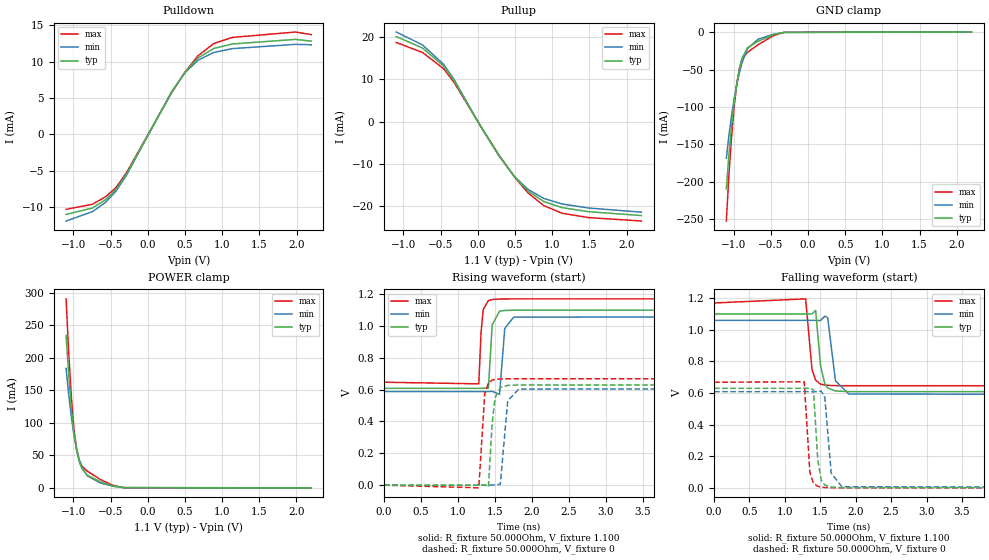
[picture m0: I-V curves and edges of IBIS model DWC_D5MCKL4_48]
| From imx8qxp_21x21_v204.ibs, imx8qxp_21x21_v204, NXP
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[Model] DWC_D5MCKL4_48
Model_type   I/O
Polarity   Non-Inverting
Enable   Active-High
C_comp   1.321pF   1.237pF   1.427pF
C_comp_pullup   305.148fF   286.138fF   319.726fF
C_comp_pulldown 1.003pF   942.855fF   1.120pF
Vinh = 396.000mV
Vinl = 216.000mV
Vmeas = 306.000mV
Vref = 306.000mV
Rref = 50Ohms
Cref = 0pF
[Model Spec]
Vinh   396.000mV   384.000mV   415.000mV
Vinl   216.000mV   204.000mV   235.000mV
Vmeas   306.000mV   294.000mV   325.000mV
Vref   306.000mV   294.000mV   325.000mV
D_overshoot_ampl_h 0.35 NA   NA
D_overshoot_ampl_l 0.35 NA   NA
D_overshoot_area_l 800.000p NA   NA
D_overshoot_area_h 800.000p NA   NA
[Receiver Thresholds]
Vcross_low = 211.000mV
Vcross_high = 401.000mV
Vdiff_ac = 140.000mV
Vdiff_dc = 140.000mV
Tdiffslew_ac = 10.000ns
[Temperature Range]   25.000   125.000   -40.000
[Voltage Range]   1.100V   1.060V   1.170V
[GND Clamp Reference]   0.00V   0.00V   0.00V
|[C Comp Corner]
| variable   typ   min   max
|C_comp 1.321pF   1.427pF   1.237pF
|C_comp_pullup 305.148fF   319.726fF   286.138fF
|C_comp_pulldown 1.003pF   1.120pF   942.855fF
[Pulldown Reference]   0.00V   0.00V   0.00V
[POWER Clamp Reference]   1.100V   1.060V   1.170V
[Pullup Reference]   1.100V   1.060V   1.170V
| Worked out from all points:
|   slope of the pulldown table from 0 to 0.165 V, typ, clamps not added: 53.8 ohm
|   slope of the pullup table from 0 to 0.165 V, typ, clamps not added: 34.5 ohm
|   GND clamp passes 1 mA (typ) near -0.36 V on its own axis
|   POWER clamp passes 1 mA (typ) near -0.39 V on its own axis
|   rising waveform, R_fixture 50.000Ohm, V_fixture 1.100: 20-80 % time 38.2ps typ, 43.8ps min, 35.6ps max; typ from 0.608 V to 1.1 V
|   rising waveform, R_fixture 50.000Ohm, V_fixture 0: 20-80 % time 54.8ps typ, 62.8ps min, 48.9ps max; typ from 0 V to 0.63 V
|   falling waveform, R_fixture 50.000Ohm, V_fixture 1.100: 20-80 % time 72.5ps typ, 82.2ps min, 66ps max; typ from 1.1 V to 0.608 V
|   falling waveform, R_fixture 50.000Ohm, V_fixture 0: 20-80 % time 54.3ps typ, 63.4ps min, 47.8ps max; typ from 0.63 V to 0 V
[GND Clamp]
-1.099V   -209.2mA   -168.4mA   -252.1mA
-1.064V   -163.4mA   -137.7mA   -190.3mA
-1.028V   -124.9mA   -111.2mA   -139.2mA
-992.7mV  -93.53mA   -88.68mA   -98.97mA
-957.3mV  -68.45mA   -69.71mA   -68.58mA
-921.8mV  -48.89mA   -53.8mA    -47.45mA
-886.4mV  -34.72mA   -40.61mA   -35.66mA
-815.5mV  -21.1mA    -22.26mA   -27.15mA
-673.6mV  -12.42mA   -9.691mA   -17.09mA
-460.9mV  -3.348mA   -2.898mA   -4.568mA
-319.1mV  -385.7uA   -561.1uA   -390.5uA
2.198V    36.46nA    642nA      5.339nA
[Power Clamp]
-1.098V   234.6mA    183.9mA    290.8mA
-1.063V   174.2mA    143.9mA    208.3mA
-1.027V   123.2mA    109.2mA    139.7mA
-991.8mV  84.12mA    80.63mA    90.23mA
-956.4mV  57.38mA    58.87mA    59.68mA
-920.9mV  40.3mA     43.02mA    42.62mA
-885.5mV  29.76mA    31.87mA    33.77mA
-814.5mV  19.66mA    18.65mA    25.86mA
-637.3mV  9.272mA    7.463mA    12.87mA
-460mV    2.471mA    2.346mA    3.441mA
-318.2mV  227.1uA    402.8uA    250.8uA
2.199V    -18.43nA   -638.2nA   -2.113nA
[Pulldown]
-1.099V   -11mA      -11.9mA    -10.3mA
-744.5mV  -10.11mA   -10.61mA   -9.6mA
-567.3mV  -8.97mA    -9.324mA   -8.566mA
-425.5mV  -7.553mA   -7.776mA   -7.28mA
-283.6mV  -5.379mA   -5.558mA   -5.21mA
319.1mV   5.761mA    5.84mA     5.69mA
496.4mV   8.469mA    8.419mA    8.5mA
673.6mV   10.48mA    10.17mA    10.77mA
886.4mV   11.79mA    11.24mA    12.47mA
1.135V    12.41mA    11.77mA    13.31mA
1.986V    13.04mA    12.36mA    14.05mA
2.198V    12.8mA     12.3mA     13.7mA
[Pullup]
-1.098V   20.2mA     21.27mA    18.8mA
-743.6mV  17.46mA    18.21mA    16.41mA
-460mV    13.2mA     13.59mA    12.56mA
-318.2mV  9.631mA    9.952mA    9.251mA
36.4mV    -1.076mA   -1.11mA    -1.046mA
284.5mV   -8.06mA    -8.175mA   -7.95mA
497.3mV   -13.2mA    -13.13mA   -13.27mA
674.5mV   -16.48mA   -16.09mA   -16.92mA
887.3mV   -18.98mA   -18.25mA   -19.96mA
1.135V    -20.43mA   -19.56mA   -21.76mA
1.49V     -21.39mA   -20.51mA   -22.79mA
2.199V    -22.3mA    -21.5mA    -23.6mA
[Ramp]
R_load=50.000Ohm
dV/dt_r   336.540mV/47.500ps  324.179mV/54.000ps  357.570mV/43.500ps
dV/dt_f   336.540mV/64.500ps  324.209mV/73.500ps  357.570mV/58.000ps
[Rising waveform]
R_fixture=50.000Ohm
V_fixture=1.100
V_fixture_min=1.060
V_fixture_max=1.170
0s        608.3mV    588.1mV    646.5mV
1.283ns   608.2mV    588.1mV    636.4mV
1.313ns   608.3mV    588.1mV    956.1mV
1.343ns   609.3mV    588.1mV    1.103V
1.413ns   609mV      588mV      1.16V
1.464ns   1.007V     589.4mV    1.166V
1.564ns   1.093V     569.7mV    1.169V
1.634ns   1.097V     983.8mV    1.169V
1.754ns   1.099V     1.055V     1.17V
10ns      1.1V       1.06V      1.17V
[Rising waveform]
R_fixture=50.000Ohm
V_fixture=0
0s        139.5nV    4.128uV    20.06nV
1.283ns   -42.78uV   4.932uV    -16.83mV
1.363ns   1.5mV      -8.145uV   573.4mV
1.413ns   -10.97mV   -119.2uV   643.5mV
1.464ns   389.1mV    983.5uV    659.8mV
1.504ns   550.2mV    1.243mV    664mV
1.574ns   614.2mV    5.149mV    666.7mV
1.674ns   626.7mV    529.7mV    667.9mV
1.824ns   629.2mV    603.1mV    668.4mV
10ns      630.1mV    608.7mV    668.4mV
[Falling waveform]
R_fixture=50.000Ohm
V_fixture=1.100
V_fixture_min=1.060
V_fixture_max=1.170
0s        1.1V       1.06V      1.17V
1.293ns   1.1V       1.06V      1.196V
1.383ns   1.101V     1.06V      748.4mV
1.434ns   1.123V     1.06V      681.2mV
1.504ns   771.7mV    1.059V     656.2mV
1.564ns   657.9mV    1.087V     650.4mV
1.604ns   632.3mV    1.077V     648.8mV
1.714ns   613.2mV    676.9mV    647mV
1.904ns   609mV      593.8mV    646.3mV
10ns      608.2mV    588mV      646.4mV
[Falling waveform]
R_fixture=50.000Ohm
V_fixture=0
0s        630mV      608.7mV    668.3mV
1.273ns   630mV      608.7mV    671.1mV
1.353ns   630.1mV    608.7mV    96.78mV
1.403ns   620.4mV    608.7mV    29.34mV
1.464ns   179mV      608.3mV    9.65mV
1.514ns   48.39mV    612.6mV    4.55mV
1.564ns   18mV       572.3mV    2.3mV
1.654ns   5.236mV    93mV       761.5uV
1.804ns   1.084mV    7.236mV    152.7uV
10ns      394.6nV    4.162uV    59.28nV
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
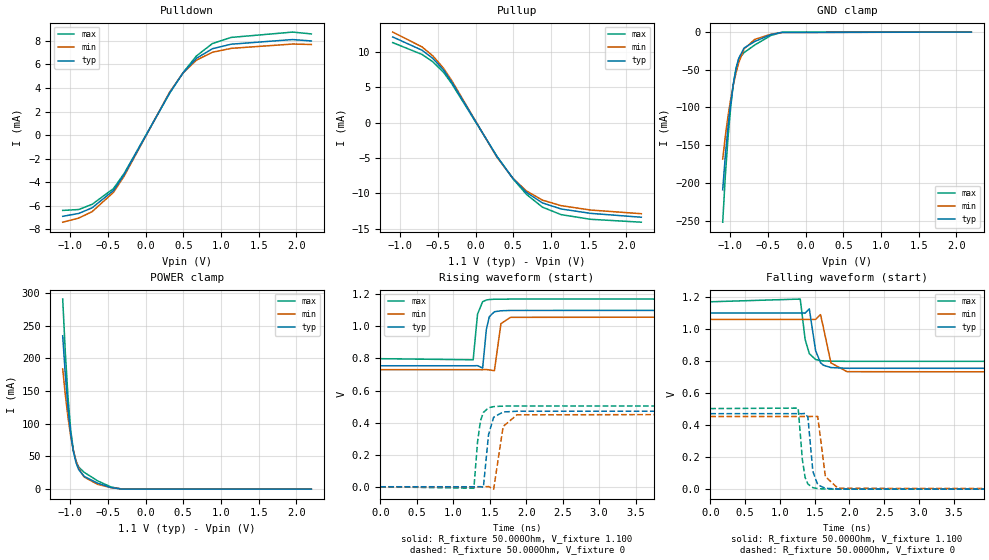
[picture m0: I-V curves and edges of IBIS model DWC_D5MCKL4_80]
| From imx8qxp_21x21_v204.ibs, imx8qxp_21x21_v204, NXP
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[Model] DWC_D5MCKL4_80
Model_type   I/O
Polarity   Non-Inverting
Enable   Active-High
C_comp   1.321pF   1.237pF   1.427pF
C_comp_pullup   304.579fF   285.377fF   319.196fF
C_comp_pulldown 1.005pF   946.034fF   1.122pF
Vinh = 390.000mV
Vinl = 210.000mV
Vmeas = 300.000mV
Vref = 300.000mV
Rref = 50Ohms
Cref = 0pF
[Model Spec]
Vinh   390.000mV   379.000mV   409.000mV
Vinl   210.000mV   199.000mV   229.000mV
Vmeas   300.000mV   289.000mV   319.000mV
Vref   300.000mV   289.000mV   319.000mV
D_overshoot_ampl_h 0.35 NA   NA
D_overshoot_ampl_l 0.35 NA   NA
D_overshoot_area_l 800.000p NA   NA
D_overshoot_area_h 800.000p NA   NA
[Receiver Thresholds]
Vcross_low = 205.000mV
Vcross_high = 395.000mV
Vdiff_ac = 140.000mV
Vdiff_dc = 140.000mV
Tdiffslew_ac = 10.000ns
[Temperature Range]   25.000   125.000   -40.000
[Voltage Range]   1.100V   1.060V   1.170V
[GND Clamp Reference]   0.00V   0.00V   0.00V
|[C Comp Corner]
| variable   typ   min   max
|C_comp 1.321pF   1.427pF   1.237pF
|C_comp_pullup 304.579fF   319.196fF   285.377fF
|C_comp_pulldown 1.005pF   1.122pF   946.034fF
[Pulldown Reference]   0.00V   0.00V   0.00V
[POWER Clamp Reference]   1.100V   1.060V   1.170V
[Pullup Reference]   1.100V   1.060V   1.170V
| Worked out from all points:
|   slope of the pulldown table from 0 to 0.165 V, typ, clamps not added: 86.4 ohm
|   slope of the pullup table from 0 to 0.165 V, typ, clamps not added: 57.5 ohm
|   GND clamp passes 1 mA (typ) near -0.36 V on its own axis
|   POWER clamp passes 1 mA (typ) near -0.39 V on its own axis
|   rising waveform, R_fixture 50.000Ohm, V_fixture 1.100: 20-80 % time 48.7ps typ, 54.4ps min, 45.9ps max; typ from 0.754 V to 1.1 V
|   rising waveform, R_fixture 50.000Ohm, V_fixture 0: 20-80 % time 71.6ps typ, 80.5ps min, 65ps max; typ from 0 V to 0.471 V
|   falling waveform, R_fixture 50.000Ohm, V_fixture 1.100: 20-80 % time 85.2ps typ, 95.9ps min, 79.5ps max; typ from 1.1 V to 0.754 V
|   falling waveform, R_fixture 50.000Ohm, V_fixture 0: 20-80 % time 64ps typ, 73.8ps min, 57.6ps max; typ from 0.471 V to 0 V
[GND Clamp]
-1.099V   -209.2mA   -168.4mA   -252.1mA
-1.064V   -163.4mA   -137.7mA   -190.3mA
-1.028V   -124.9mA   -111.2mA   -139.2mA
-992.7mV  -93.53mA   -88.68mA   -98.97mA
-957.3mV  -68.45mA   -69.71mA   -68.58mA
-921.8mV  -48.89mA   -53.8mA    -47.45mA
-886.4mV  -34.72mA   -40.61mA   -35.66mA
-815.5mV  -21.1mA    -22.26mA   -27.15mA
-673.6mV  -12.42mA   -9.691mA   -17.09mA
-460.9mV  -3.348mA   -2.898mA   -4.568mA
-319.1mV  -385.7uA   -561.1uA   -390.5uA
2.198V    36.46nA    642nA      5.339nA
[Power Clamp]
-1.098V   234.6mA    183.9mA    290.8mA
-1.063V   174.2mA    143.9mA    208.3mA
-1.027V   123.2mA    109.2mA    139.7mA
-991.8mV  84.12mA    80.63mA    90.23mA
-956.4mV  57.38mA    58.87mA    59.68mA
-920.9mV  40.3mA     43.02mA    42.62mA
-885.5mV  29.76mA    31.87mA    33.77mA
-814.5mV  19.66mA    18.65mA    25.86mA
-637.3mV  9.272mA    7.463mA    12.87mA
-460mV    2.471mA    2.346mA    3.441mA
-318.2mV  227.1uA    402.8uA    250.8uA
2.199V    -18.43nA   -638.2nA   -2.113nA
[Pulldown]
-1.099V   -6.9mA     -7.4mA     -6.4mA
-886.4mV  -6.658mA   -7.05mA    -6.323mA
-709.1mV  -6.179mA   -6.505mA   -5.883mA
-425.5mV  -4.706mA   -4.866mA   -4.544mA
-283.6mV  -3.353mA   -3.477mA   -3.253mA
319.1mV   3.591mA    3.654mA    3.552mA
496.4mV   5.277mA    5.269mA    5.306mA
673.6mV   6.526mA    6.368mA    6.724mA
886.4mV   7.34mA     7.038mA    7.781mA
1.135V    7.725mA    7.372mA    8.301mA
1.95V     8.12mA     7.738mA    8.754mA
2.198V    8mA        7.7mA      8.6mA
[Pullup]
-1.098V   12.1mA     12.79mA    11.3mA
-708.2mV  10.22mA    10.69mA    9.626mA
-566.4mV  9.072mA    9.431mA    8.592mA
-424.5mV  7.435mA    7.687mA    7.106mA
-318.2mV  5.772mA    5.99mA     5.553mA
284.5mV   -4.83mA    -4.92mA    -4.772mA
497.3mV   -7.909mA   -7.898mA   -7.961mA
674.5mV   -9.874mA   -9.678mA   -10.15mA
887.3mV   -11.37mA   -10.98mA   -11.97mA
1.135V    -12.23mA   -11.76mA   -13.03mA
1.526V    -12.85mA   -12.38mA   -13.69mA
2.199V    -13.4mA    -12.9mA    -14.1mA
[Ramp]
R_load=50.000Ohm
dV/dt_r   245.130mV/60.500ps  235.168mV/68.500ps  262.470mV/56.000ps
dV/dt_f   245.100mV/75.500ps  235.168mV/86.000ps  262.470mV/69.500ps
[Rising waveform]
R_fixture=50.000Ohm
V_fixture=1.100
V_fixture_min=1.060
V_fixture_max=1.170
0s        754.3mV    729.9mV    798.4mV
1.273ns   754.3mV    729.9mV    791.5mV
1.333ns   754.8mV    729.9mV    1.076V
1.403ns   740mV      729.8mV    1.154V
1.454ns   981.2mV    730.7mV    1.164V
1.494ns   1.06V      728.4mV    1.167V
1.564ns   1.091V     723.6mV    1.169V
1.654ns   1.097V     1.017V     1.169V
1.784ns   1.099V     1.056V     1.17V
10ns      1.1V       1.06V      1.17V
[Rising waveform]
R_fixture=50.000Ohm
V_fixture=0
0s        170.7nV    5.063uV    24.44nV
1.283ns   -33.32uV   5.741uV    -9.412mV
1.333ns   263.4uV    21.19uV    279.3mV
1.373ns   429uV      -23.08uV   410.8mV
1.413ns   -3.922mV   -91.12uV   463.2mV
1.484ns   325.6mV    1.08mV     492.4mV
1.554ns   433.7mV    -15.02mV   499.7mV
1.684ns   466.1mV    376.2mV    502.8mV
1.874ns   470.7mV    448.4mV    503.5mV
10ns      471.4mV    453.8mV    503.3mV
[Falling waveform]
R_fixture=50.000Ohm
V_fixture=1.100
V_fixture_min=1.060
V_fixture_max=1.170
0s        1.1V       1.06V      1.17V
1.293ns   1.1V       1.06V      1.187V
1.363ns   1.099V     1.06V      935.2mV
1.423ns   1.126V     1.06V      846mV
1.514ns   864.3mV    1.06V      809.7mV
1.584ns   790mV      1.09V      802.6mV
1.624ns   774.2mV    1.012V     800.9mV
1.734ns   759.2mV    788.1mV    799mV
1.965ns   754.8mV    733.7mV    798.2mV
10ns      754.3mV    729.8mV    798.3mV
[Falling waveform]
R_fixture=50.000Ohm
V_fixture=0
0s        471.3mV    453.7mV    503.2mV
1.263ns   471.3mV    453.7mV    506.2mV
1.323ns   471.2mV    453.7mV    186.6mV
1.363ns   472.8mV    453.7mV    72.43mV
1.403ns   449.3mV    453.7mV    31.85mV
1.474ns   111.8mV    453.9mV    9.481mV
1.544ns   27.15mV    453.7mV    3.436mV
1.654ns   5.633mV    78.82mV    846uV
1.834ns   837.6uV    5.569mV    118.7uV
10ns      308.7nV    5.349uV    127.6nV
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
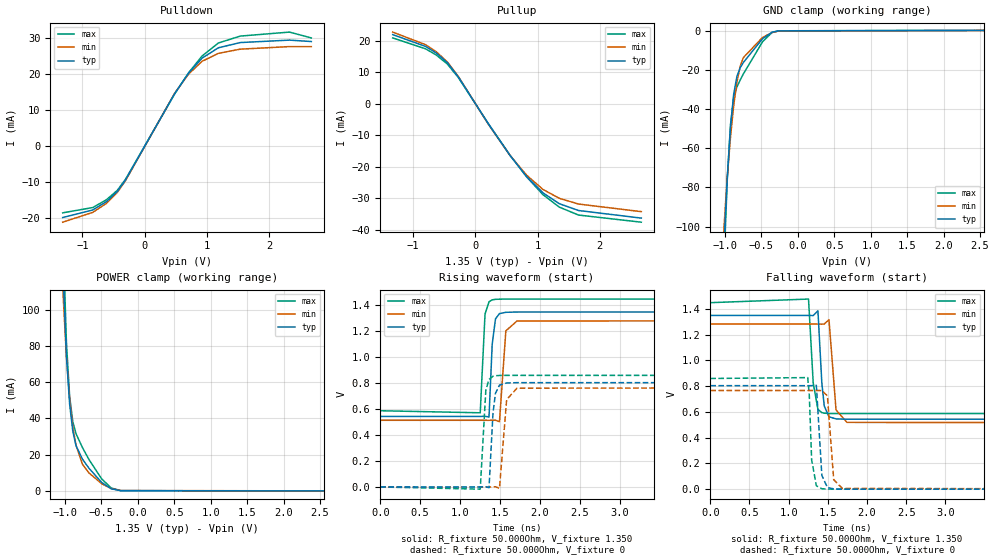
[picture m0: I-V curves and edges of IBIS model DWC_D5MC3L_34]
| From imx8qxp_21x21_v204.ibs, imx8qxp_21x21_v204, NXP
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[Model] DWC_D5MC3L_34
Model_type   I/O
Polarity   Non-Inverting
Enable   Active-High
C_comp   1.262pF   1.180pF   1.365pF
C_comp_pullup   279.441fF   258.852fF   306.885fF
C_comp_pulldown 973.651fF   908.565fF   1.053pF
Vinh = 800.000mV
Vinl = 550.000mV
Vmeas = 675.000mV
Vref = 675.000mV
Rref = 50Ohms
Cref = 0pF
[Model Spec]
Vinh   800.000mV   766.500mV   850.000mV
Vinl   550.000mV   516.500mV   600.000mV
Vmeas   675.000mV   641.500mV   725.000mV
Vref   675.000mV   641.500mV   725.000mV
D_overshoot_ampl_h 0.4 NA   NA
D_overshoot_ampl_l 0.4 NA   NA
D_overshoot_area_l 100.000p NA   NA
D_overshoot_area_h 100.000p NA   NA
[Receiver Thresholds]
Vth = 675.000mV
Vth_min = 661.500mV
Vth_max = 688.500mV
Vinh_ac = 125.000mV
Vinh_dc = 90.000mV
Vinl_ac = -125.000mV
Vinl_dc = -90.000mV
Tslew_ac = 5.000ns
Threshold_sensitivity = 0.5
Reference_supply Pullup_ref
[Temperature Range]   25.000   125.000   -40.000
[Voltage Range]   1.350V   1.283V   1.450V
[GND Clamp Reference]   0.00V   0.00V   0.00V
|[C Comp Corner]
| variable   typ   min   max
|C_comp 1.262pF   1.365pF   1.180pF
|C_comp_pullup 279.441fF   306.885fF   258.852fF
|C_comp_pulldown 973.651fF   1.053pF   908.565fF
[Pulldown Reference]   0.00V   0.00V   0.00V
[POWER Clamp Reference]   1.350V   1.283V   1.450V
[Pullup Reference]   1.350V   1.283V   1.450V
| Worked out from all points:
|   slope of the pulldown table from 0 to 0.203 V, typ, clamps not added: 32.3 ohm
|   slope of the pullup table from 0 to 0.203 V, typ, clamps not added: 32.7 ohm
|   GND clamp passes 1 mA (typ) near -0.36 V on its own axis
|   POWER clamp passes 1 mA (typ) near -0.36 V on its own axis
|   rising waveform, R_fixture 50.000Ohm, V_fixture 1.350: 20-80 % time 37ps typ, 42.6ps min, 34.5ps max; typ from 0.544 V to 1.35 V
|   rising waveform, R_fixture 50.000Ohm, V_fixture 0: 20-80 % time 44.6ps typ, 52.6ps min, 41ps max; typ from 0 V to 0.804 V
|   falling waveform, R_fixture 50.000Ohm, V_fixture 1.350: 20-80 % time 47.4ps typ, 53.9ps min, 44.2ps max; typ from 1.35 V to 0.544 V
|   falling waveform, R_fixture 50.000Ohm, V_fixture 0: 20-80 % time 38.8ps typ, 45.4ps min, 35.4ps max; typ from 0.804 V to 0 V
[GND Clamp]
-1.318V   -593.4mA   -427mA     -758.7mA
-1.011V   -108.7mA   -99.8mA    -118.2mA
-966.7mV  -74.7mA    -74.6mA    -75.87mA
-922.7mV  -49.41mA   -54.3mA    -47.9mA
-878.8mV  -32.42mA   -38.21mA   -34.12mA
-834.8mV  -23.33mA   -26.23mA   -28.72mA
-790.9mV  -19.01mA   -18.35mA   -25.26mA
-747mV    -16.25mA   -13.76mA   -22.11mA
-483.3mV  -4.093mA   -3.434mA   -5.633mA
-351.5mV  -766.8uA   -911.3uA   -894.7uA
-263.6mV  -79.41uA   -192.1uA   -51.43uA
2.68V     154.9uA    127.3uA    193.1uA
[Power Clamp]
-1.33V    727.8mA    510.6mA    954.1mA
-1.023V   119.4mA    107.4mA    137.5mA
-978.8mV  74.87mA    74.2mA     82.23mA
-934.8mV  47.95mA    50.66mA    52.21mA
-890.9mV  32.9mA     35.12mA    38.1mA
-847mV    24.9mA     25.11mA    31.53mA
-759.1mV  17.5mA     14.71mA    23.9mA
-671.2mV  12.54mA    9.915mA    17.38mA
-495.5mV  4.603mA    3.922mA    6.563mA
-363.6mV  1.088mA    1.21mA     1.541mA
-231.8mV  46.56uA    141.4uA    53.69uA
2.668V    -76.24uA   -66.58uA   -87.76uA
[Pulldown]
-1.318V   -20mA      -21.3mA    -18.7mA
-834.8mV  -17.9mA    -18.57mA   -17.23mA
-615.2mV  -15.6mA    -16.07mA   -15.07mA
-439.4mV  -12.76mA   -13.01mA   -12.44mA
-307.6mV  -9.544mA   -9.743mA   -9.357mA
483.3mV   14.46mA    14.56mA    14.37mA
703mV     20.04mA    19.79mA    20.15mA
922.7mV   24.29mA    23.41mA    24.89mA
1.186V    27.17mA    25.62mA    28.5mA
1.538V    28.62mA    26.79mA    30.42mA
2.329V    29.3mA     27.5mA     31.53mA
2.68V     28.9mA     27.5mA     29.9mA
[Pullup]
-1.33V    22mA       22.8mA     20.95mA
-803mV    18.26mA    18.81mA    17.5mA
-627.3mV  16.13mA    16.52mA    15.49mA
-451.5mV  13.09mA    13.31mA    12.65mA
-275.8mV  8.586mA    8.754mA    8.383mA
207.6mV   -6.353mA   -6.458mA   -6.264mA
559.1mV   -16.46mA   -16.46mA   -16.39mA
822.7mV   -23.06mA   -22.65mA   -23.2mA
1.086V    -28.28mA   -27.19mA   -28.85mA
1.35V     -31.73mA   -30.02mA   -32.82mA
1.658V    -33.89mA   -31.83mA   -35.33mA
2.668V    -36.3mA    -34.25mA   -37.6mA
[Ramp]
R_load=50.000Ohm
dV/dt_r   482.550mV/41.000ps  460.168mV/48.000ps  515.970mV/38.000ps
dV/dt_f   482.550mV/43.500ps  460.198mV/49.500ps  515.970mV/40.000ps
[Rising waveform]
R_fixture=50.000Ohm
V_fixture=1.350
V_fixture_min=1.283
V_fixture_max=1.450
0s        543.7mV    513.9mV    587.5mV
1.253ns   543.7mV    513.9mV    571.7mV
1.313ns   544.8mV    513.9mV    1.332V
1.363ns   539.3mV    513.8mV    1.427V
1.403ns   1.099V     514.3mV    1.442V
1.444ns   1.295V     514.3mV    1.446V
1.494ns   1.336V     503.5mV    1.447V
1.574ns   1.346V     1.203V     1.448V
1.714ns   1.348V     1.279V     1.448V
10ns      1.349V     1.282V     1.448V
[Rising waveform]
R_fixture=50.000Ohm
V_fixture=0
0s        353.8nV    7.444uV    47.1nV
1.253ns   5.716uV    6.285uV    -16.79mV
1.323ns   1.561mV    21.94uV    744.3mV
1.363ns   -5.911mV   -83.11uV   829.4mV
1.413ns   569.6mV    673.4uV    853.1mV
1.444ns   722.2mV    1.526mV    857.1mV
1.494ns   784.8mV    -10.79mV   859.4mV
1.584ns   801.6mV    672.9mV    860.1mV
1.714ns   803.9mV    761.3mV    860.1mV
10ns      803.7mV    766mV      859.5mV
[Falling waveform]
R_fixture=50.000Ohm
V_fixture=1.350
V_fixture_min=1.283
V_fixture_max=1.450
0s        1.349V     1.282V     1.448V
1.253ns   1.349V     1.282V     1.476V
1.313ns   1.348V     1.282V     823.8mV
1.373ns   1.385V     1.282V     619.3mV
1.423ns   822.6mV    1.281V     594.4mV
1.454ns   645.3mV    1.282V     590mV
1.514ns   561.8mV    1.316V     587.4mV
1.604ns   545.6mV    615.1mV    586.8mV
1.744ns   543.3mV    518.2mV    586.7mV
10ns      543.6mV    513.8mV    587.4mV
[Falling waveform]
R_fixture=50.000Ohm
V_fixture=0
0s        803.6mV    766mV      859.4mV
1.243ns   803.5mV    766mV      866.2mV
1.263ns   803.6mV    766mV      728.8mV
1.293ns   803.5mV    766mV      227.1mV
1.353ns   805.8mV    766mV      26.75mV
1.423ns   106.7mV    765.5mV    3.619mV
1.494ns   12.92mV    724.6mV    554.2uV
1.574ns   2.201mV    74.43mV    70.96uV
1.684ns   233.3uV    5.586mV    9.729uV
10ns      679.5nV    7.715uV    283.7nV
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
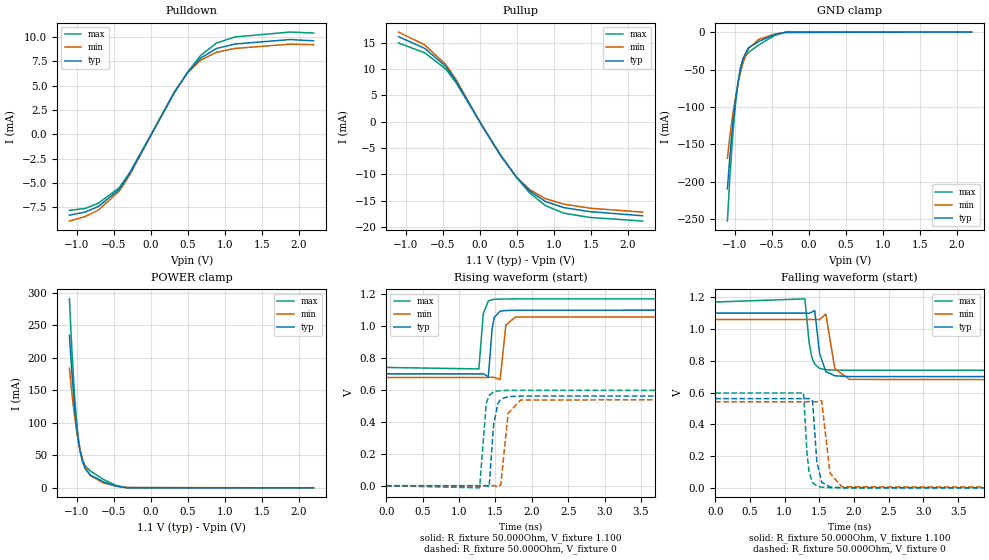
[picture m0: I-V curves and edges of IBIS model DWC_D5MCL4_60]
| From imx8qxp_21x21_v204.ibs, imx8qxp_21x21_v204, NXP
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[Model] DWC_D5MCL4_60
Model_type   I/O
Polarity   Non-Inverting
Enable   Active-High
C_comp   1.321pF   1.237pF   1.427pF
C_comp_pullup   306.026fF   287.268fF   320.532fF
C_comp_pulldown 1.001pF   938.298fF   1.118pF
Vinh = 404.000mV
Vinl = 224.000mV
Vmeas = 314.000mV
Vref = 314.000mV
Rref = 50Ohms
Cref = 0pF
[Model Spec]
Vinh   404.000mV   393.000mV   424.000mV
Vinl   224.000mV   213.000mV   244.000mV
Vmeas   314.000mV   303.000mV   334.000mV
Vref   314.000mV   303.000mV   334.000mV
[Receiver Thresholds]
Vth = 314.000mV
Vth_min = 303.000mV
Vth_max = 325.000mV
Vinh_ac = 70.000mV
Vinh_dc = 70.000mV
Vinl_ac = -70.000mV
Vinl_dc = -70.000mV
Tslew_ac = 5.000ns
Reference_supply Pullup_ref
[Temperature Range]   25.000   125.000   -40.000
[Voltage Range]   1.100V   1.060V   1.170V
[GND Clamp Reference]   0.00V   0.00V   0.00V
[Pulldown Reference]   0.00V   0.00V   0.00V
[POWER Clamp Reference]   1.100V   1.060V   1.170V
[Pullup Reference]   1.100V   1.060V   1.170V
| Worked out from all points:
|   slope of the pulldown table from 0 to 0.165 V, typ, clamps not added: 72 ohm
|   slope of the pullup table from 0 to 0.165 V, typ, clamps not added: 43.1 ohm
|   GND clamp passes 1 mA (typ) near -0.36 V on its own axis
|   POWER clamp passes 1 mA (typ) near -0.39 V on its own axis
|   rising waveform, R_fixture 50.000Ohm, V_fixture 1.100: 20-80 % time 42.7ps typ, 48.1ps min, 40ps max; typ from 0.7 V to 1.1 V
|   rising waveform, R_fixture 50.000Ohm, V_fixture 0: 20-80 % time 61.6ps typ, 70.6ps min, 55.8ps max; typ from 0 V to 0.562 V
|   falling waveform, R_fixture 50.000Ohm, V_fixture 1.100: 20-80 % time 81.5ps typ, 90.8ps min, 74.3ps max; typ from 1.1 V to 0.7 V
|   falling waveform, R_fixture 50.000Ohm, V_fixture 0: 20-80 % time 60.2ps typ, 69.6ps min, 53.5ps max; typ from 0.562 V to 0 V
[GND Clamp]
-1.099V   -209.2mA   -168.4mA   -252.1mA
-1.064V   -163.4mA   -137.7mA   -190.3mA
-1.028V   -124.9mA   -111.2mA   -139.2mA
-992.7mV  -93.53mA   -88.68mA   -98.97mA
-957.3mV  -68.45mA   -69.71mA   -68.58mA
-921.8mV  -48.89mA   -53.8mA    -47.45mA
-886.4mV  -34.72mA   -40.61mA   -35.66mA
-815.5mV  -21.1mA    -22.26mA   -27.15mA
-673.6mV  -12.42mA   -9.691mA   -17.09mA
-460.9mV  -3.348mA   -2.898mA   -4.568mA
-319.1mV  -385.7uA   -561.1uA   -390.5uA
2.198V    36.46nA    642nA      5.34nA
[Power Clamp]
-1.098V   234.6mA    183.9mA    290.8mA
-1.063V   174.2mA    143.9mA    208.3mA
-1.027V   123.2mA    109.2mA    139.7mA
-991.8mV  84.12mA    80.63mA    90.23mA
-956.4mV  57.38mA    58.87mA    59.68mA
-920.9mV  40.3mA     43.02mA    42.62mA
-885.5mV  29.76mA    31.87mA    33.77mA
-814.5mV  19.66mA    18.65mA    25.86mA
-637.3mV  9.272mA    7.463mA    12.87mA
-460mV    2.471mA    2.346mA    3.441mA
-318.2mV  227.1uA    402.8uA    250.8uA
2.199V    -18.43nA   -638.2nA   -2.114nA
[Pulldown]
-1.099V   -8.3mA     -8.9mA     -7.8mA
-886.4mV  -7.98mA    -8.444mA   -7.613mA
-709.1mV  -7.415mA   -7.784mA   -7.08mA
-425.5mV  -5.647mA   -5.823mA   -5.47mA
-283.6mV  -4.023mA   -4.162mA   -3.916mA
319.1mV   4.308mA    4.374mA    4.276mA
496.4mV   6.332mA    6.305mA    6.387mA
673.6mV   7.83mA     7.618mA    8.094mA
886.4mV   8.808mA    8.418mA    9.366mA
1.135V    9.27mA     8.817mA    9.991mA
1.879V    9.729mA    9.256mA    10.5mA
2.198V    9.6mA      9.2mA      10.4mA
[Pullup]
-1.098V   16.2mA     17.07mA    15mA
-743.6mV  13.97mA    14.62mA    13.12mA
-460mV    10.56mA    10.91mA    10.05mA
-318.2mV  7.71mA     7.989mA    7.404mA
36.4mV    -861.2uA   -890.7uA   -837.3uA
284.5mV   -6.452mA   -6.562mA   -6.362mA
497.3mV   -10.57mA   -10.53mA   -10.62mA
674.5mV   -13.2mA    -12.91mA   -13.54mA
887.3mV   -15.19mA   -14.65mA   -15.97mA
1.135V    -16.35mA   -15.69mA   -17.4mA
1.49V     -17.12mA   -16.46mA   -18.22mA
2.199V    -17.9mA    -17.21mA   -18.9mA
[Ramp]
R_load=50.000Ohm
dV/dt_r   288.630mV/53.000ps  277.409mV/60.500ps  308.010mV/49.000ps
dV/dt_f   288.600mV/71.500ps  277.378mV/80.500ps  308.010mV/64.500ps
[Rising waveform]
R_fixture=50.000Ohm
V_fixture=1.100
V_fixture_min=1.060
V_fixture_max=1.170
0s        700.1mV    677.9mV    740.6mV
1.273ns   700.1mV    677.9mV    731.4mV
1.333ns   700.7mV    677.9mV    1.078V
1.403ns   682.6mV    677.9mV    1.157V
1.454ns   980.6mV    678.9mV    1.165V
1.484ns   1.054V     678mV      1.167V
1.564ns   1.093V     664.1mV    1.169V
1.644ns   1.097V     1.007V     1.169V
1.774ns   1.099V     1.056V     1.17V
10ns      1.1V       1.06V      1.17V
[Rising waveform]
R_fixture=50.000Ohm
V_fixture=0
0s        159nV      4.711uV    22.78nV
1.283ns   -38.75uV   5.44uV     -13.34mV
1.373ns   625.5uV    -28.1uV    513.6mV
1.413ns   -8.049mV   -107.3uV   565.1mV
1.474ns   376.1mV    1.143mV    587.8mV
1.534ns   516mV      -6.508mV   593.7mV
1.574ns   541.4mV    4.836mV    595.2mV
1.674ns   557.7mV    452.9mV    596.8mV
1.844ns   561.4mV    536.8mV    597.4mV
10ns      562.2mV    542.6mV    597.3mV
[Falling waveform]
R_fixture=50.000Ohm
V_fixture=1.100
V_fixture_min=1.060
V_fixture_max=1.170
0s        1.1V       1.06V      1.17V
1.293ns   1.1V       1.06V      1.19V
1.353ns   1.099V     1.06V      916.2mV
1.393ns   1.107V     1.06V      822.1mV
1.434ns   1.117V     1.06V      778.9mV
1.504ns   847mV      1.059V     752.5mV
1.594ns   732.1mV    1.094V     743.8mV
1.724ns   705.5mV    750.7mV    741.1mV
1.935ns   700.8mV    682.9mV    740.3mV
10ns      700.1mV    677.9mV    740.5mV
[Falling waveform]
R_fixture=50.000Ohm
V_fixture=0
0s        562.1mV    542.5mV    597.2mV
1.273ns   562.1mV    542.5mV    597.5mV
1.323ns   561.9mV    542.5mV    216.4mV
1.353ns   562.3mV    542.5mV    99.98mV
1.403ns   546.3mV    542.5mV    33.31mV
1.464ns   167.8mV    542.2mV    11.31mV
1.534ns   35.1mV     549.7mV    4.017mV
1.654ns   5.95mV     92.55mV    871.9uV
1.824ns   989.9uV    6.625mV    138.5uV
10ns      592nV      5.198uV    167.7nV
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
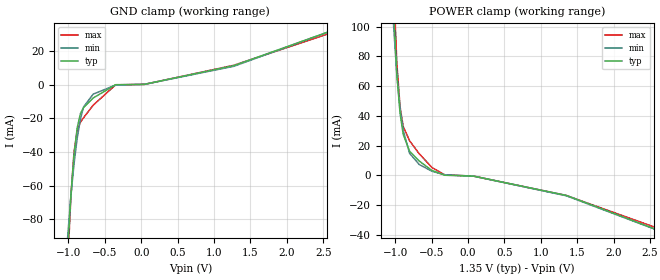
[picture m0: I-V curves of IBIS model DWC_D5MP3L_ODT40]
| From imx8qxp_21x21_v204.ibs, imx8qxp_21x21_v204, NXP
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[Model] DWC_D5MP3L_ODT40
Model_type   Input
Polarity   Non-Inverting
Enable   Active-High
C_comp   1.357pF   1.333pF   1.413pF
C_comp_power_clamp   387.694fF   369.914fF   419.877fF
C_comp_gnd_clamp 960.640fF   900.161fF   1.038pF
Vinh = 800.000mV
Vinl = 550.000mV
[Model Spec]
D_overshoot_ampl_h 0.4 NA   NA
D_overshoot_ampl_l 0.4 NA   NA
D_overshoot_area_l 100.000p NA   NA
D_overshoot_area_h 100.000p NA   NA
[Receiver Thresholds]
Vth = 675.000mV
Vth_min = 661.500mV
Vth_max = 688.500mV
Vinh_ac = 125.000mV
Vinh_dc = 90.000mV
Vinl_ac = -125.000mV
Vinl_dc = -90.000mV
Tslew_ac = 5.000ns
Threshold_sensitivity = 0.5
Reference_supply Power_clamp_ref
[Temperature Range]   25.000   125.000   -40.000
[Voltage Range]   1.350V   1.283V   1.450V
[GND Clamp Reference]   0.00V   0.00V   0.00V
[POWER Clamp Reference]   1.350V   1.283V   1.450V
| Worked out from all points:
|   GND clamp passes 1 mA (typ) near -0.43 V on its own axis
|   POWER clamp passes 1 mA (typ) near -0.40 V on its own axis
[GND Clamp]
-1.318V   -579.5mA   -413.7mA   -744.6mA
-1.011V   -99.9mA    -91.36mA   -109.1mA
-966.7mV  -66.5mA    -66.83mA   -67.5mA
-922.7mV  -41.88mA   -47.17mA   -40.22mA
-878.8mV  -25.54mA   -31.72mA   -27.11mA
-834.8mV  -17.09mA   -20.36mA   -22.34mA
-790.9mV  -13.39mA   -13.07mA   -19.5mA
-659.1mV  -7.784mA   -5.455mA   -12.06mA
-351.5mV  156.3uA    -72.56uA   68.25uA
43.94mV   369.5uA    370.1uA    360uA
1.274V    11.56mA    11.16mA    11.77mA
2.68V     33.33mA    33.38mA    32.14mA
[Power Clamp]
-1.33V    716.6mA    499.8mA    942.7mA
-1.023V   112.3mA    100.7mA    130.4mA
-978.8mV  68.35mA    68.06mA    75.76mA
-934.8mV  42.03mA    45.11mA    46.37mA
-890.9mV  27.53mA    30.11mA    32.83mA
-803mV    16.17mA    14.73mA    23.17mA
-671.2mV  9.588mA    7.238mA    14.48mA
-495.5mV  3.174mA    2.671mA    5.181mA
-319.7mV  -5.401uA   294.3uA    256uA
75.8mV    -611.5uA   -621.5uA   -603.4uA
1.35V     -13.58mA   -13.85mA   -13.67mA
2.668V    -38.13mA   -38.28mA   -36.81mA
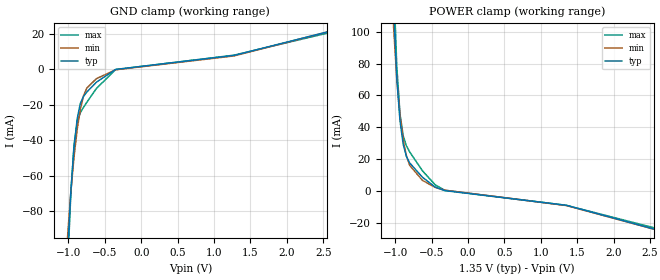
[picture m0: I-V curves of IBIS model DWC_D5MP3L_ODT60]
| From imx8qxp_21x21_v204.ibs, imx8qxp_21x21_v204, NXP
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[Model] DWC_D5MP3L_ODT60
Model_type   Input
Polarity   Non-Inverting
Enable   Active-High
C_comp   1.324pF   1.278pF   1.395pF
C_comp_power_clamp   350.581fF   346.965fF   363.631fF
C_comp_gnd_clamp 964.349fF   901.632fF   1.044pF
Vinh = 800.000mV
Vinl = 550.000mV
[Model Spec]
D_overshoot_ampl_h 0.4 NA   NA
D_overshoot_ampl_l 0.4 NA   NA
D_overshoot_area_l 100.000p NA   NA
D_overshoot_area_h 100.000p NA   NA
[Receiver Thresholds]
Vth = 675.000mV
Vth_min = 661.500mV
Vth_max = 688.500mV
Vinh_ac = 125.000mV
Vinh_dc = 90.000mV
Vinl_ac = -125.000mV
Vinl_dc = -90.000mV
Tslew_ac = 5.000ns
Threshold_sensitivity = 0.5
Reference_supply Power_clamp_ref
[Temperature Range]   25.000   125.000   -40.000
[Voltage Range]   1.350V   1.283V   1.450V
[GND Clamp Reference]   0.00V   0.00V   0.00V
[POWER Clamp Reference]   1.350V   1.283V   1.450V
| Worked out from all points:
|   GND clamp passes 1 mA (typ) near -0.41 V on its own axis
|   POWER clamp passes 1 mA (typ) near -0.38 V on its own axis
[GND Clamp]
-1.318V   -584.3mA   -418.1mA   -749.5mA
-1.011V   -102.9mA   -94.23mA   -112.2mA
-966.7mV  -69.27mA   -69.45mA   -70.32mA
-922.7mV  -44.41mA   -49.57mA   -42.8mA
-878.8mV  -27.85mA   -33.9mA    -29.45mA
-834.8mV  -19.18mA   -22.33mA   -24.47mA
-790.9mV  -15.27mA   -14.84mA   -21.42mA
-747mV    -12.91mA   -10.63mA   -18.66mA
-615.2mV  -7.33mA    -5.36mA    -10.9mA
-351.5mV  -151.6uA   -354.8uA   -251.7uA
1.274V    7.715mA    7.454mA    7.873mA
2.68V     22.27mA    22.24mA    21.49mA
[Power Clamp]
-1.33V    720.4mA    503.5mA    946.7mA
-1.023V   114.7mA    103mA      132.9mA
-978.8mV  70.55mA    70.17mA    77.96mA
-934.8mV  44.01mA    46.99mA    48.31mA
-890.9mV  29.32mA    31.8mA     34.57mA
-847mV    21.66mA    22.12mA    28.34mA
-803mV    17.61mA    16.08mA    24.56mA
-627.3mV  8.605mA    6.649mA    12.68mA
-451.5mV  2.386mA    2.18mA     3.777mA
-319.7mV  163.2uA    425.6uA    396uA
1.35V     -9.051mA   -9.206mA   -9.09mA
2.668V    -25.42mA   -25.5mA    -24.53mA
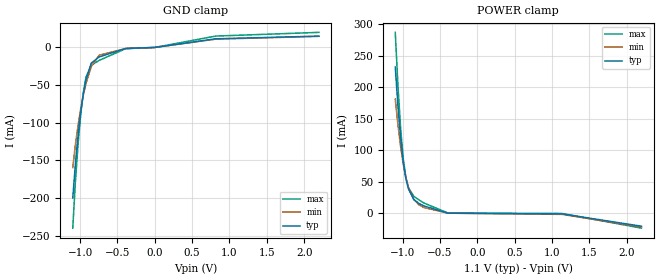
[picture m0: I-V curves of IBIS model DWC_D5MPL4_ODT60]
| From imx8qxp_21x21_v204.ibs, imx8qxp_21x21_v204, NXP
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[Model] DWC_D5MPL4_ODT60
Model_type   Input
Polarity   Non-Inverting
Enable   Active-High
C_comp   1.284pF   1.202pF   1.378pF
C_comp_power_clamp   319.771fF   299.116fF   341.733fF
C_comp_gnd_clamp 947.165fF   886.520fF   1.045pF
Vinh = 640.000mV
Vinl = 460.000mV
[Model Spec]
D_overshoot_ampl_h 0.35 NA   NA
D_overshoot_ampl_l 0.35 NA   NA
D_overshoot_area_l 800.000p NA   NA
D_overshoot_area_h 800.000p NA   NA
[Receiver Thresholds]
Vth = 550.000mV
Vth_min = 539.000mV
Vth_max = 561.000mV
Vinh_ac = 70.000mV
Vinh_dc = 70.000mV
Vinl_ac = -70.000mV
Vinl_dc = -70.000mV
Tslew_ac = 5.000ns
Reference_supply Power_clamp_ref
[Temperature Range]   25.000   125.000   -40.000
[Voltage Range]   1.100V   1.060V   1.170V
[GND Clamp Reference]   0.00V   0.00V   0.00V
[POWER Clamp Reference]   1.100V   1.060V   1.170V
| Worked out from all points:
|   GND clamp passes 1 mA (typ) near -0.36 V on its own axis
|   POWER clamp passes 1 mA (typ) near -0.42 V on its own axis
[GND Clamp]
-1.099V   -200mA     -159.7mA   -240.1mA
-1.064V   -154.9mA   -129.6mA   -179.2mA
-1.028V   -117mA     -103.7mA   -128.9mA
-992.7mV  -86.18mA   -81.72mA   -89.38mA
-957.3mV  -61.73mA   -63.33mA   -59.77mA
-921.8mV  -42.74mA   -47.96mA   -39.39mA
-850.9mV  -20.84mA   -25.3mA    -23.65mA
-744.5mV  -12.6mA    -10.28mA   -17.19mA
-390mV    -1.396mA   -1.485mA   -1.627mA
-1.5uV    -17.22uA   -25.9uA    -13.98uA
815.5mV   11.47mA    10.98mA    15.08mA
2.198V    15.04mA    14.73mA    20mA
[Power Clamp]
-1.098V   232.4mA    181.6mA    287.4mA
-1.063V   172mA      141.7mA    205.1mA
-1.027V   121.1mA    107mA      136.8mA
-991.8mV  82.25mA    78.61mA    87.63mA
-956.4mV  55.67mA    56.97mA    57.38mA
-920.9mV  38.71mA    41.23mA    40.52mA
-850mV    22.08mA    22.46mA    27.29mA
-779.1mV  15.79mA    13.54mA    21.41mA
-708.2mV  11.79mA    9.151mA    16.29mA
-389.1mV  460.3uA    514uA      605uA
1.135V    -634uA     -1.388mA   -10.09uA
2.199V    -20.17mA   -21.32mA   -23.25mA
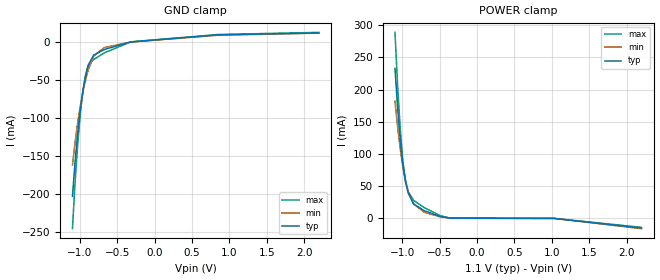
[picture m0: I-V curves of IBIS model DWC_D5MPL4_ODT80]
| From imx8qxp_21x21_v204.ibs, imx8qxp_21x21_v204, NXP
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[Model] DWC_D5MPL4_ODT80
Model_type   Input
Polarity   Non-Inverting
Enable   Active-High
C_comp   1.294pF   1.215pF   1.390pF
C_comp_power_clamp   319.453fF   298.227fF   339.681fF
C_comp_gnd_clamp 953.531fF   893.694fF   1.054pF
Vinh = 640.000mV
Vinl = 460.000mV
[Model Spec]
D_overshoot_ampl_h 0.35 NA   NA
D_overshoot_ampl_l 0.35 NA   NA
D_overshoot_area_l 800.000p NA   NA
D_overshoot_area_h 800.000p NA   NA
[Receiver Thresholds]
Vth = 550.000mV
Vth_min = 539.000mV
Vth_max = 561.000mV
Vinh_ac = 70.000mV
Vinh_dc = 70.000mV
Vinl_ac = -70.000mV
Vinl_dc = -70.000mV
Tslew_ac = 5.000ns
Reference_supply Power_clamp_ref
[Temperature Range]   25.000   125.000   -40.000
[Voltage Range]   1.100V   1.060V   1.170V
[GND Clamp Reference]   0.00V   0.00V   0.00V
[POWER Clamp Reference]   1.100V   1.060V   1.170V
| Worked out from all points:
|   GND clamp passes 1 mA (typ) near -0.36 V on its own axis
|   POWER clamp passes 1 mA (typ) near -0.41 V on its own axis
[GND Clamp]
-1.099V   -202.4mA   -161.9mA   -245mA
-1.064V   -157mA     -131.7mA   -183.7mA
-1.028V   -119mA     -105.6mA   -133.1mA
-992.7mV  -88.08mA   -83.48mA   -93.24mA
-957.3mV  -63.42mA   -64.93mA   -63.31mA
-921.8mV  -44.29mA   -49.43mA   -42.62mA
-886.4mV  -30.54mA   -36.64mA   -31.26mA
-815.5mV  -17.71mA   -19.05mA   -23.53mA
-673.6mV  -10.44mA   -7.867mA   -14.9mA
-319.1mV  -501.2uA   -730.3uA   -436.8uA
850.9mV   8.697mA    8.328mA    9.214mA
2.198V    11.23mA    11.03mA    11.95mA
[Power Clamp]
-1.098V   233mA      182.2mA    288.9mA
-1.063V   172.6mA    142.2mA    206.6mA
-1.027V   121.6mA    107.6mA    138.2mA
-991.8mV  82.73mA    79.12mA    88.73mA
-956.4mV  56.11mA    57.44mA    58.35mA
-920.9mV  39.12mA    41.67mA    41.39mA
-850mV    22.44mA    22.86mA    28.03mA
-708.2mV  12.07mA    9.466mA    16.88mA
-495.5mV  2.994mA    2.525mA    4.378mA
-353.6mV  175.4uA    293.2uA    284.5uA
1.029V    -4.88nA    -30.81uA   -650.8pA
2.199V    -15.08mA   -15.97mA   -13.95mA
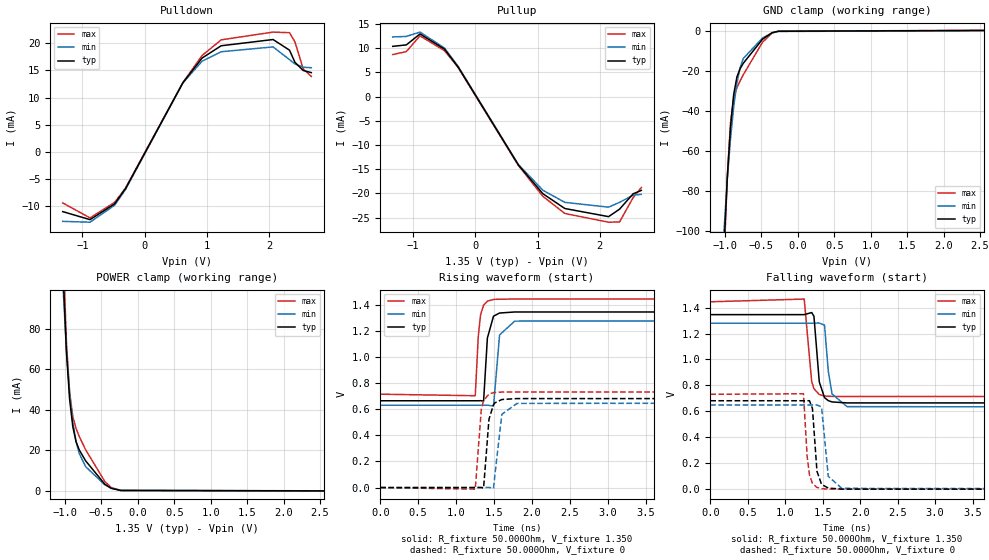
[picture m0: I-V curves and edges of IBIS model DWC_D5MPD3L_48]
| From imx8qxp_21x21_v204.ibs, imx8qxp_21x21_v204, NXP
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[Model] DWC_D5MPD3L_48
Model_type   I/O
Polarity   Non-Inverting
Enable   Active-High
C_comp   1.451pF   1.359pF   1.565pF
C_comp_pullup   315.783fF   294.189fF   344.067fF
C_comp_pulldown 1.109pF   1.032pF   1.207pF
Vinh = 800.000mV
Vinl = 550.000mV
Vmeas = 675.000mV
Vref = 675.000mV
Rref = 50Ohms
Cref = 0pF
[Model Spec]
Vinh   800.000mV   767.000mV   850.000mV
Vinl   550.000mV   517.000mV   600.000mV
Vmeas   675.000mV   642.000mV   725.000mV
Vref   675.000mV   642.000mV   725.000mV
D_overshoot_ampl_h 0.4 NA   NA
D_overshoot_ampl_l 0.4 NA   NA
D_overshoot_area_l 100.000p NA   NA
D_overshoot_area_h 100.000p NA   NA
[Receiver Thresholds]
Vcross_low = 525.000mV
Vcross_high = 825.000mV
Vdiff_ac = 250.000mV
Vdiff_dc = 180.000mV
Tdiffslew_ac = 10.000ns
[Temperature Range]   25.000   125.000   -40.000
[Voltage Range]   1.350V   1.283V   1.450V
[GND Clamp Reference]   0.00V   0.00V   0.00V
[Pulldown Reference]   0.00V   0.00V   0.00V
[POWER Clamp Reference]   1.350V   1.283V   1.450V
[Pullup Reference]   1.350V   1.283V   1.450V
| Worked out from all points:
|   slope of the pulldown table from 0 to 0.203 V, typ, clamps not added: 45.6 ohm
|   slope of the pullup table from 0 to 0.203 V, typ, clamps not added: 46.1 ohm
|   GND clamp passes 1 mA (typ) near -0.36 V on its own axis
|   POWER clamp passes 1 mA (typ) near -0.36 V on its own axis
|   rising waveform, R_fixture 50.000Ohm, V_fixture 1.350: 20-80 % time 48.7ps typ, 53.3ps min, 46.3ps max; typ from 0.665 V to 1.35 V
|   rising waveform, R_fixture 50.000Ohm, V_fixture 0: 20-80 % time 59.6ps typ, 67.8ps min, 55.6ps max; typ from 0 V to 0.682 V
|   falling waveform, R_fixture 50.000Ohm, V_fixture 1.350: 20-80 % time 64.7ps typ, 72.2ps min, 60.3ps max; typ from 1.35 V to 0.665 V
|   falling waveform, R_fixture 50.000Ohm, V_fixture 0: 20-80 % time 51.5ps typ, 58.2ps min, 47.1ps max; typ from 0.682 V to 0 V
[GND Clamp]
-1.318V   -611.9mA   -435.6mA   -789.4mA
-1.011V   -107.3mA   -99.44mA   -114.7mA
-966.7mV  -73.21mA   -74.14mA   -72.86mA
-922.7mV  -48.19mA   -53.84mA   -45.97mA
-878.8mV  -31.65mA   -37.83mA   -33.26mA
-834.8mV  -22.94mA   -25.98mA   -28.23mA
-790.9mV  -18.78mA   -18.21mA   -24.87mA
-747mV    -16.07mA   -13.69mA   -21.78mA
-483.3mV  -4.069mA   -3.422mA   -5.579mA
-351.5mV  -769.8uA   -913.6uA   -898.3uA
-263.6mV  -80.12uA   -193.4uA   -52.02uA
2.68V     309.8uA    252.8uA    386uA
[Power Clamp]
-1.33V    624.3mA    459.2mA    781.3mA
-1.023V   106.8mA    99.48mA    118.2mA
-978.8mV  68.81mA    69.68mA    73.53mA
-934.8mV  45.17mA    48.25mA    48.62mA
-890.9mV  31.58mA    33.85mA    36.56mA
-847mV    24.24mA    24.41mA    30.7mA
-803mV    20.11mA    18.35mA    26.81mA
-715.2mV  14.71mA    11.84mA    20.17mA
-451.5mV  3.129mA    2.823mA    4.473mA
-363.6mV  1.086mA    1.21mA     1.534mA
-231.8mV  46.56uA    141.6uA    53.57uA
2.668V    -152.4uA   -131.4uA   -175.4uA
[Pulldown]
-1.318V   -11mA      -12.8mA    -9.4mA
-878.8mV  -12.48mA   -12.95mA   -12.16mA
-483.3mV  -9.577mA   -9.83mA    -9.3mA
-307.6mV  -6.763mA   -6.915mA   -6.649mA
615.2mV   12.74mA    12.72mA    12.78mA
922.7mV   17.28mA    16.7mA     17.75mA
1.23V     19.55mA    18.45mA    20.64mA
2.065V    20.7mA     19.34mA    22.07mA
2.329V    18.74mA    17mA       21.96mA
2.417V    16.5mA     16.2mA     20.26mA
2.549V    15mA       15.6mA     15.3mA
2.68V     14.6mA     15.5mA     13.9mA
[Pullup]
-1.33V    10.4mA     12.35mA    8.7mA
-1.111V   10.7mA     12.45mA    9.317mA
-890.9mV  12.97mA    13.35mA    12.57mA
-495.5mV  9.809mA    10.04mA    9.49mA
-275.8mV  6.08mA     6.209mA    5.976mA
690.9mV   -14.13mA   -14.04mA   -14.23mA
1.086V    -20.09mA   -19.37mA   -20.64mA
1.438V    -23.14mA   -21.87mA   -24.17mA
2.141V    -24.82mA   -22.86mA   -25.97mA
2.317V    -23.29mA   -21.87mA   -25.93mA
2.536V    -20.1mA    -20.39mA   -20.9mA
2.668V    -19.4mA    -20.2mA    -18.81mA
[Ramp]
R_load=50.000Ohm
dV/dt_r   408.870mV/54.500ps  389.637mV/61.000ps  438.360mV/51.500ps
dV/dt_f   408.870mV/58.500ps  389.637mV/66.000ps  438.330mV/54.000ps
[Rising waveform]
R_fixture=50.000Ohm
V_fixture=1.350
V_fixture_min=1.283
V_fixture_max=1.450
0s        665.4mV    631.1mV    715.8mV
1.253ns   665.4mV    631.1mV    703.9mV
1.293ns   665.4mV    631.1mV    1.159V
1.323ns   666.3mV    631.1mV    1.324V
1.363ns   662.4mV    631mV      1.398V
1.413ns   1.146V     631.9mV    1.429V
1.494ns   1.314V     624.9mV    1.442V
1.574ns   1.338V     1.17V      1.444V
1.774ns   1.346V     1.276V     1.445V
10ns      1.346V     1.28V      1.445V
[Rising waveform]
R_fixture=50.000Ohm
V_fixture=0
0s        424.9nV    8.934uV    58.17nV
1.253ns   8.424uV    5.377uV    -12.28mV
1.333ns   319.2uV    16.32uV    602.2mV
1.363ns   -3.915mV   -67.08uV   666.2mV
1.434ns   523.2mV    1.357mV    716.9mV
1.494ns   636mV      -5.998mV   727.8mV
1.514ns   649.9mV    107mV      729.4mV
1.604ns   675mV      561.4mV    732.1mV
1.804ns   682.2mV    645mV      732.7mV
10ns      682mV      649.7mV    731.9mV
[Falling waveform]
R_fixture=50.000Ohm
V_fixture=1.350
V_fixture_min=1.283
V_fixture_max=1.450
0s        1.346V     1.28V      1.445V
1.253ns   1.346V     1.28V      1.466V
1.353ns   1.362V     1.28V      829.1mV
1.383ns   1.333V     1.28V      775mV
1.454ns   827.2mV    1.281V     729.6mV
1.524ns   705.9mV    1.265V     718.7mV
1.574ns   682.6mV    911.2mV    716.3mV
1.624ns   672.8mV    734.4mV    715.4mV
1.824ns   665.2mV    636.5mV    714.8mV
10ns      665.3mV    631mV      715.6mV
[Falling waveform]
R_fixture=50.000Ohm
V_fixture=0
0s        681.9mV    649.6mV    731.6mV
1.243ns   681.9mV    649.6mV    735.8mV
1.293ns   681.8mV    649.6mV    248.5mV
1.323ns   682.1mV    649.6mV    110.1mV
1.363ns   622mV      649.7mV    44.37mV
1.423ns   138.3mV    649.4mV    13.14mV
1.484ns   37.42mV    634.3mV    3.992mV
1.574ns   8.267mV    99.35mV    718.4uV
1.754ns   494.9uV    6.125mV    48.9uV
10ns      602.2nV    9.179uV    185nV
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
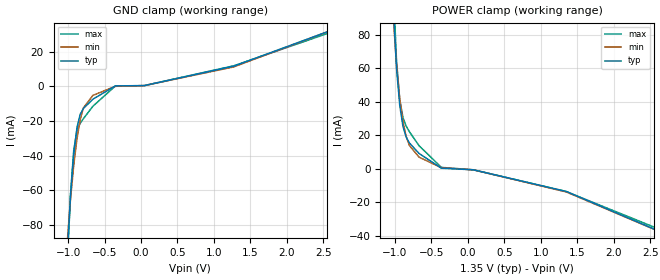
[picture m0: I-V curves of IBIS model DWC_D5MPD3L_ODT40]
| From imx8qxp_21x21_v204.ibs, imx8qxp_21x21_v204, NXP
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[Model] DWC_D5MPD3L_ODT40
Model_type   Input
Polarity   Non-Inverting
Enable   Active-High
C_comp   1.536pF   1.503pF   1.600pF
C_comp_power_clamp   422.724fF   403.548fF   454.961fF
C_comp_gnd_clamp 1.087pF   1.015pF   1.182pF
Vinh = 800.000mV
Vinl = 550.000mV
[Model Spec]
D_overshoot_ampl_h 0.4 NA   NA
D_overshoot_ampl_l 0.4 NA   NA
D_overshoot_area_l 100.000p NA   NA
D_overshoot_area_h 100.000p NA   NA
[Receiver Thresholds]
Vcross_low = 525.000mV
Vcross_high = 825.000mV
Vdiff_ac = 250.000mV
Vdiff_dc = 180.000mV
Tdiffslew_ac = 10.000ns
[Temperature Range]   25.000   125.000   -40.000
[Voltage Range]   1.350V   1.283V   1.450V
[GND Clamp Reference]   0.00V   0.00V   0.00V
[POWER Clamp Reference]   1.350V   1.283V   1.450V
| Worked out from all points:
|   GND clamp passes 1 mA (typ) near -0.44 V on its own axis
|   POWER clamp passes 1 mA (typ) near -0.41 V on its own axis
[GND Clamp]
-1.318V   -592.2mA   -418.5mA   -767.7mA
-1.011V   -95.96mA   -89.33mA   -102.4mA
-966.7mV  -63.15mA   -65.01mA   -62.26mA
-922.7mV  -39.32mA   -45.63mA   -36.97mA
-878.8mV  -23.94mA   -30.49mA   -25.65mA
-834.8mV  -16.26mA   -19.49mA   -21.45mA
-790.9mV  -12.86mA   -12.54mA   -18.74mA
-659.1mV  -7.449mA   -5.252mA   -11.5mA
-351.5mV  205.6uA    -32.76uA   145.8uA
43.94mV   370.9uA    371.2uA    362.6uA
1.274V    11.59mA    11.18mA    11.82mA
2.68V     33.37mA    33.38mA    32.23mA
[Power Clamp]
-1.33V    606.2mA    443.8mA    761.3mA
-1.023V   96.23mA    90.3mA     106.8mA
-978.8mV  60.02mA    61.72mA    64.51mA
-934.8mV  37.88mA    41.44mA    41.42mA
-890.9mV  25.43mA    27.99mA    30.59mA
-847mV    18.94mA    19.36mA    25.49mA
-803mV    15.47mA    13.98mA    22.17mA
-671.2mV  9.205mA    6.984mA    13.85mA
-363.6mV  359uA      619.4uA    835.9uA
75.8mV    -609.5uA   -619.3uA   -601.8uA
1.35V     -13.52mA   -13.8mA    -13.61mA
2.668V    -38.07mA   -38.21mA   -36.78mA
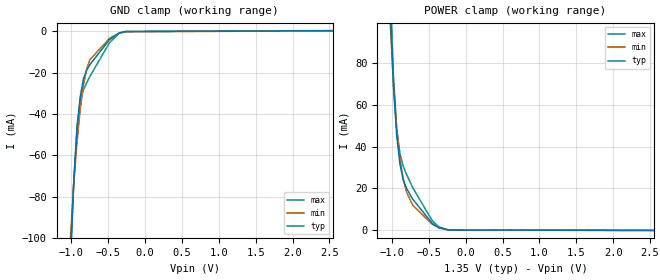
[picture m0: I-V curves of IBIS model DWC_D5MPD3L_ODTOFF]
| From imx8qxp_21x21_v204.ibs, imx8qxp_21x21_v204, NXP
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[Model] DWC_D5MPD3L_ODTOFF
Model_type   Input
Polarity   Non-Inverting
Enable   Active-High
C_comp   1.451pF   1.359pF   1.565pF
C_comp_power_clamp   315.783fF   294.189fF   344.067fF
C_comp_gnd_clamp 1.109pF   1.032pF   1.207pF
Vinh = 800.000mV
Vinl = 550.000mV
[Model Spec]
D_overshoot_ampl_h 0.4 NA   NA
D_overshoot_ampl_l 0.4 NA   NA
D_overshoot_area_l 100.000p NA   NA
D_overshoot_area_h 100.000p NA   NA
[Receiver Thresholds]
Vcross_low = 525.000mV
Vcross_high = 825.000mV
Vdiff_ac = 250.000mV
Vdiff_dc = 180.000mV
Tdiffslew_ac = 10.000ns
[Temperature Range]   25.000   125.000   -40.000
[Voltage Range]   1.350V   1.283V   1.450V
[GND Clamp Reference]   0.00V   0.00V   0.00V
[POWER Clamp Reference]   1.350V   1.283V   1.450V
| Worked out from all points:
|   GND clamp passes 1 mA (typ) near -0.36 V on its own axis
|   POWER clamp passes 1 mA (typ) near -0.36 V on its own axis
[GND Clamp]
-1.318V   -611.9mA   -435.6mA   -789.4mA
-1.011V   -107.3mA   -99.44mA   -114.7mA
-966.7mV  -73.21mA   -74.14mA   -72.86mA
-922.7mV  -48.19mA   -53.84mA   -45.97mA
-878.8mV  -31.65mA   -37.83mA   -33.26mA
-834.8mV  -22.94mA   -25.98mA   -28.23mA
-790.9mV  -18.78mA   -18.21mA   -24.87mA
-747mV    -16.07mA   -13.69mA   -21.78mA
-483.3mV  -4.069mA   -3.422mA   -5.579mA
-351.5mV  -769.8uA   -913.6uA   -898.3uA
-263.6mV  -80.12uA   -193.4uA   -52.02uA
2.68V     309.8uA    252.8uA    386uA
[Power Clamp]
-1.33V    624.3mA    459.2mA    781.3mA
-1.023V   106.8mA    99.48mA    118.2mA
-978.8mV  68.81mA    69.68mA    73.53mA
-934.8mV  45.17mA    48.25mA    48.62mA
-890.9mV  31.58mA    33.85mA    36.56mA
-847mV    24.24mA    24.41mA    30.7mA
-803mV    20.11mA    18.35mA    26.81mA
-715.2mV  14.71mA    11.84mA    20.17mA
-451.5mV  3.129mA    2.823mA    4.473mA
-363.6mV  1.086mA    1.21mA     1.534mA
-231.8mV  46.56uA    141.6uA    53.57uA
2.668V    -152.4uA   -131.4uA   -175.4uA
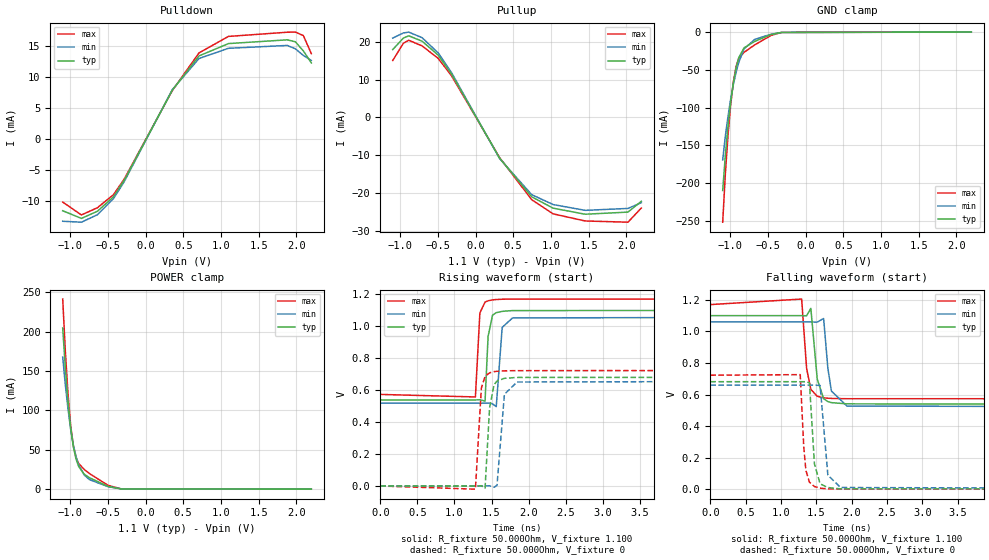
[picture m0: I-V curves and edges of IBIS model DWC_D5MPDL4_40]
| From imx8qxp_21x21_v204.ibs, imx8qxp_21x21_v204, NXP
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[Model] DWC_D5MPDL4_40
Model_type   I/O
Polarity   Non-Inverting
Enable   Active-High
C_comp   1.573pF   1.476pF   1.691pF
C_comp_pullup   365.888fF   348.771fF   366.657fF
C_comp_pulldown 1.177pF   1.110pF   1.347pF
Vinh = 390.000mV
Vinl = 210.000mV
Vmeas = 300.000mV
Vref = 300.000mV
Rref = 50Ohms
Cref = 0pF
[Model Spec]
Vinh   390.000mV   379.000mV   409.000mV
Vinl   210.000mV   199.000mV   229.000mV
Vmeas   300.000mV   289.000mV   319.000mV
Vref   300.000mV   289.000mV   319.000mV
D_overshoot_ampl_h 0.35 NA   NA
D_overshoot_ampl_l 0.35 NA   NA
D_overshoot_area_l 800.000p NA   NA
D_overshoot_area_h 800.000p NA   NA
[Receiver Thresholds]
Vcross_low = 205.000mV
Vcross_high = 395.000mV
Vdiff_ac = 140.000mV
Vdiff_dc = 140.000mV
Tdiffslew_ac = 10.000ns
[Temperature Range]   25.000   125.000   -40.000
[Voltage Range]   1.100V   1.060V   1.170V
[GND Clamp Reference]   0.00V   0.00V   0.00V
[Pulldown Reference]   0.00V   0.00V   0.00V
[POWER Clamp Reference]   1.100V   1.060V   1.170V
[Pullup Reference]   1.100V   1.060V   1.170V
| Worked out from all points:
|   slope of the pulldown table from 0 to 0.165 V, typ, clamps not added: 43.3 ohm
|   slope of the pullup table from 0 to 0.165 V, typ, clamps not added: 29 ohm
|   GND clamp passes 1 mA (typ) near -0.36 V on its own axis
|   POWER clamp passes 1 mA (typ) near -0.39 V on its own axis
|   rising waveform, R_fixture 50.000Ohm, V_fixture 1.100: 20-80 % time 38.5ps typ, 43.8ps min, 36.3ps max; typ from 0.539 V to 1.1 V
|   rising waveform, R_fixture 50.000Ohm, V_fixture 0: 20-80 % time 54.3ps typ, 61.5ps min, 49.4ps max; typ from 0 V to 0.681 V
|   falling waveform, R_fixture 50.000Ohm, V_fixture 1.100: 20-80 % time 73.5ps typ, 82.4ps min, 67.8ps max; typ from 1.1 V to 0.539 V
|   falling waveform, R_fixture 50.000Ohm, V_fixture 0: 20-80 % time 56ps typ, 63.7ps min, 50.3ps max; typ from 0.681 V to 0 V
[GND Clamp]
-1.099V   -209.8mA   -169.1mA   -251.7mA
-1.064V   -162.7mA   -137.8mA   -187.8mA
-1.028V   -123.6mA   -111mA     -135.8mA
-992.7mV  -92.04mA   -88.31mA   -95.63mA
-957.3mV  -67.05mA   -69.29mA   -65.81mA
-921.8mV  -47.73mA   -53.39mA   -45.6mA
-886.4mV  -33.92mA   -40.26mA   -34.72mA
-815.5mV  -20.84mA   -22.1mA    -26.75mA
-673.6mV  -12.32mA   -9.665mA   -16.87mA
-460.9mV  -3.34mA    -2.899mA   -4.539mA
-319.1mV  -390.9uA   -567.4uA   -395.4uA
2.198V    38.3nA     663.5nA    7.806nA
[Power Clamp]
-1.098V   204.7mA    167.9mA    241.5mA
-1.063V   153.5mA    132.2mA    175.1mA
-1.027V   110.2mA    101.3mA    120.2mA
-991.8mV  76.87mA    75.61mA    80.19mA
-956.4mV  53.56mA    55.87mA    54.83mA
-920.9mV  38.25mA    41.27mA    40.22mA
-885.5mV  28.61mA    30.83mA    32.49mA
-814.5mV  19.18mA    18.23mA    25.18mA
-743.6mV  14.55mA    12.13mA    19.82mA
-495.5mV  3.463mA    3.102mA    4.838mA
-318.2mV  225.2uA    399.5uA    248.6uA
2.199V    -19.18nA   -668.9nA   -2.436nA
[Pulldown]
-1.099V   -11.6mA    -13.3mA    -10.2mA
-850.9mV  -12.84mA   -13.45mA   -12.28mA
-638.2mV  -11.68mA   -12.24mA   -11.11mA
-425.5mV  -9.334mA   -9.64mA    -9mA
-283.6mV  -6.676mA   -6.907mA   -6.485mA
354.5mV   7.887mA    7.984mA    7.831mA
709.1mV   13.43mA    13.01mA    13.92mA
1.099V    15.42mA    14.66mA    16.58mA
1.879V    16.03mA    15.12mA    17.26mA
1.986V    15.71mA    14.59mA    17.28mA
2.092V    14.24mA    13.5mA     16.72mA
2.198V    12.3mA     12.7mA     13.8mA
[Pullup]
-1.098V   17.9mA     20.94mA    15.02mA
-956.4mV  20.95mA    22.29mA    19.57mA
-885.5mV  21.54mA    22.52mA    20.37mA
-708.2mV  20.12mA    21.04mA    18.87mA
-495.5mV  16.45mA    17.04mA    15.6mA
-318.2mV  11.45mA    11.85mA    11.01mA
320mV     -10.71mA   -10.85mA   -10.6mA
745.5mV   -20.92mA   -20.35mA   -21.68mA
1.029V    -23.91mA   -22.96mA   -25.41mA
1.455V    -25.51mA   -24.49mA   -27.29mA
2.022V    -24.95mA   -23.98mA   -27.61mA
2.199V    -22.1mA    -22.47mA   -23.87mA
[Ramp]
R_load=50.000Ohm
dV/dt_r   372.780mV/47.000ps  360.329mV/53.500ps  395.790mV/43.500ps
dV/dt_f   372.780mV/65.500ps  360.329mV/73.500ps  395.820mV/60.000ps
[Rising waveform]
R_fixture=50.000Ohm
V_fixture=1.100
V_fixture_min=1.060
V_fixture_max=1.170
0s        538.7mV    518.4mV    573.1mV
1.283ns   538.6mV    518.4mV    557.3mV
1.343ns   539.8mV    518.4mV    1.083V
1.413ns   531.2mV    518.3mV    1.151V
1.454ns   936.5mV    519.4mV    1.159V
1.514ns   1.069V     514.1mV    1.165V
1.564ns   1.085V     496.7mV    1.167V
1.644ns   1.093V     992.6mV    1.169V
1.784ns   1.098V     1.052V     1.17V
10ns      1.1V       1.06V      1.17V
[Rising waveform]
R_fixture=50.000Ohm
V_fixture=0
0s        124.1nV    3.639uV    19.67nV
1.283ns   -41.89uV   1.883uV    -19.94mV
1.363ns   1.619mV    -6.169uV   613mV
1.413ns   -13.84mV   -129.8uV   685.6mV
1.474ns   487.7mV    1.438mV    708.4mV
1.534ns   633.7mV    -8.119mV   715.8mV
1.574ns   656.6mV    3.726mV    718mV
1.674ns   674mV      573.9mV    720.7mV
1.844ns   679.3mV    650.8mV    722.1mV
10ns      681.3mV    659.5mV    722.4mV
[Falling waveform]
R_fixture=50.000Ohm
V_fixture=1.100
V_fixture_min=1.060
V_fixture_max=1.170
0s        1.1V       1.06V      1.17V
1.293ns   1.1V       1.06V      1.205V
1.363ns   1.099V     1.06V      765.8mV
1.423ns   1.146V     1.06V      632.6mV
1.514ns   696.9mV    1.059V     588.8mV
1.604ns   573.6mV    1.082V     579.1mV
1.664ns   555.1mV    766.6mV    576.5mV
1.714ns   548.5mV    622.1mV    575.2mV
1.935ns   540.6mV    526.8mV    573.2mV
10ns      538.6mV    518.4mV    573mV
[Falling waveform]
R_fixture=50.000Ohm
V_fixture=0
0s        681.2mV    659.5mV    722.4mV
1.273ns   681.2mV    659.5mV    725.9mV
1.323ns   681.1mV    659.5mV    267mV
1.353ns   681.1mV    659.5mV    119.1mV
1.403ns   675.2mV    659.6mV    45.29mV
1.474ns   159.6mV    659.3mV    16.76mV
1.554ns   34.12mV    657.6mV    6.446mV
1.664ns   10.33mV    88.89mV    1.931mV
1.844ns   2.03mV     10.46mV    344.4uV
10ns      596.7nV    3.897uV    342.4nV
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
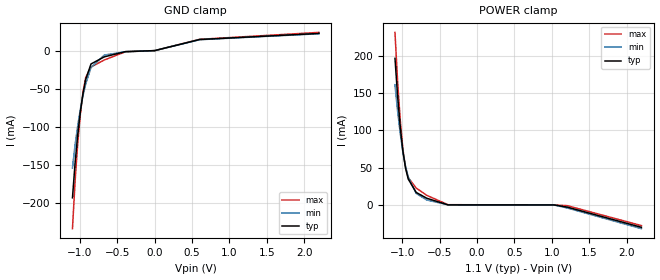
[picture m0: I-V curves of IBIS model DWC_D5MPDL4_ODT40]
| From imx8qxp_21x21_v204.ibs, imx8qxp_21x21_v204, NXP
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[Model] DWC_D5MPDL4_ODT40
Model_type   Input
Polarity   Non-Inverting
Enable   Active-High
C_comp   1.499pF   1.419pF   1.599pF
C_comp_power_clamp   376.450fF   351.078fF   388.979fF
C_comp_gnd_clamp 1.107pF   1.077pF   1.245pF
Vinh = 640.000mV
Vinl = 460.000mV
[Model Spec]
D_overshoot_ampl_h 0.35 NA   NA
D_overshoot_ampl_l 0.35 NA   NA
D_overshoot_area_l 800.000p NA   NA
D_overshoot_area_h 800.000p NA   NA
[Receiver Thresholds]
Vcross_low = 455.000mV
Vcross_high = 645.000mV
Vdiff_ac = 140.000mV
Vdiff_dc = 140.000mV
Tdiffslew_ac = 10.000ns
[Temperature Range]   25.000   125.000   -40.000
[Voltage Range]   1.100V   1.060V   1.170V
[GND Clamp Reference]   0.00V   0.00V   0.00V
[POWER Clamp Reference]   1.100V   1.060V   1.170V
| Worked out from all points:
|   GND clamp passes 1 mA (typ) near -0.36 V on its own axis
|   POWER clamp passes 1 mA (typ) near -0.44 V on its own axis
[GND Clamp]
-1.099V   -193.7mA   -154.4mA   -234.3mA
-1.064V   -147.9mA   -124.2mA   -171.9mA
-1.028V   -110.1mA   -98.47mA   -121.4mA
-992.7mV  -79.78mA   -76.86mA   -82.67mA
-957.3mV  -55.97mA   -58.84mA   -54.16mA
-921.8mV  -37.76mA   -43.92mA   -35.25mA
-850.9mV  -17.58mA   -22.19mA   -21.58mA
-673.6mV  -8.244mA   -5.919mA   -12.34mA
-390mV    -1.326mA   -1.456mA   -1.518mA
-1.5uV    -25.24uA   -37.92uA   -16.46uA
602.7mV   14.59mA    14.35mA    14.87mA
2.198V    22.58mA    22.19mA    23.96mA
[Power Clamp]
-1.098V   196.8mA    161.4mA    231.6mA
-1.063V   146.4mA    126.2mA    166.2mA
-1.027V   104.1mA    95.78mA    112.8mA
-991.8mV  71.77mA    70.75mA    74.38mA
-956.4mV  49.38mA    51.61mA    50.36mA
-920.9mV  34.78mA    37.53mA    36.68mA
-814.5mV  16.84mA    15.53mA    22.69mA
-672.7mV  9.005mA    6.699mA    12.9mA
-389.1mV  108.4uA    114.7uA    338.7uA
1.029V    -4.897nA   -61.32uA   -731pA
1.206V    -2.885mA   -4.058mA   -964.2uA
2.199V    -30.03mA   -31.83mA   -27.71mA
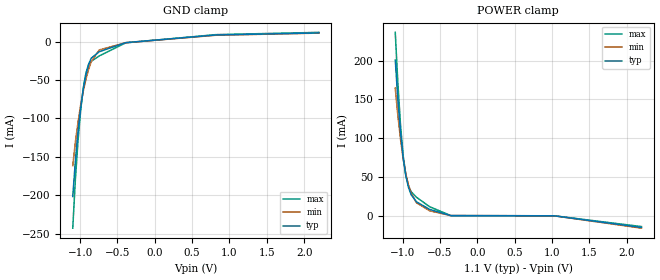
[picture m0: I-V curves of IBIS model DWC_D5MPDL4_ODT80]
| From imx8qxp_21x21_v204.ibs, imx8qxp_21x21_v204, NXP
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[Model] DWC_D5MPDL4_ODT80
Model_type   Input
Polarity   Non-Inverting
Enable   Active-High
C_comp   1.536pF   1.446pF   1.644pF
C_comp_power_clamp   385.179fF   367.216fF   391.376fF
C_comp_gnd_clamp 1.102pF   1.025pF   1.253pF
Vinh = 640.000mV
Vinl = 460.000mV
[Model Spec]
D_overshoot_ampl_h 0.35 NA   NA
D_overshoot_ampl_l 0.35 NA   NA
D_overshoot_area_l 800.000p NA   NA
D_overshoot_area_h 800.000p NA   NA
[Receiver Thresholds]
Vcross_low = 455.000mV
Vcross_high = 645.000mV
Vdiff_ac = 140.000mV
Vdiff_dc = 140.000mV
Tdiffslew_ac = 10.000ns
[Temperature Range]   25.000   125.000   -40.000
[Voltage Range]   1.100V   1.060V   1.170V
[GND Clamp Reference]   0.00V   0.00V   0.00V
[POWER Clamp Reference]   1.100V   1.060V   1.170V
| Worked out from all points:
|   GND clamp passes 1 mA (typ) near -0.36 V on its own axis
|   POWER clamp passes 1 mA (typ) near -0.42 V on its own axis
[GND Clamp]
-1.099V   -201.7mA   -161.6mA   -242.9mA
-1.064V   -155.3mA   -131mA     -179.7mA
-1.028V   -116.8mA   -104.7mA   -128.5mA
-992.7mV  -85.89mA   -82.56mA   -89.08mA
-957.3mV  -61.48mA   -64.04mA   -59.93mA
-921.8mV  -42.71mA   -48.63mA   -40.38mA
-886.4mV  -29.44mA   -35.97mA   -30.1mA
-850.9mV  -21.47mA   -25.99mA   -25.63mA
-744.5mV  -13.25mA   -10.98mA   -18.68mA
-390mV    -1.388mA   -1.467mA   -1.677mA
815.5mV   8.561mA    8.217mA    9.028mA
2.198V    11.24mA    11.05mA    11.97mA
[Power Clamp]
-1.098V   200.8mA    164.7mA    236.5mA
-1.063V   149.9mA    129.2mA    170.7mA
-1.027V   107.2mA    98.56mA    116.4mA
-991.8mV  74.33mA    73.2mA     77.28mA
-956.4mV  51.48mA    53.76mA    52.6mA
-920.9mV  36.53mA    39.41mA    38.46mA
-885.5mV  27.15mA    29.18mA    31.03mA
-814.5mV  18.03mA    16.9mA     23.94mA
-637.3mV  8.269mA    6.428mA    11.66mA
-353.6mV  144.5uA    261.4uA    238.7uA
1.029V    -4.864nA   -30.73uA   -715.3pA
2.199V    -15.04mA   -15.92mA   -13.91mA
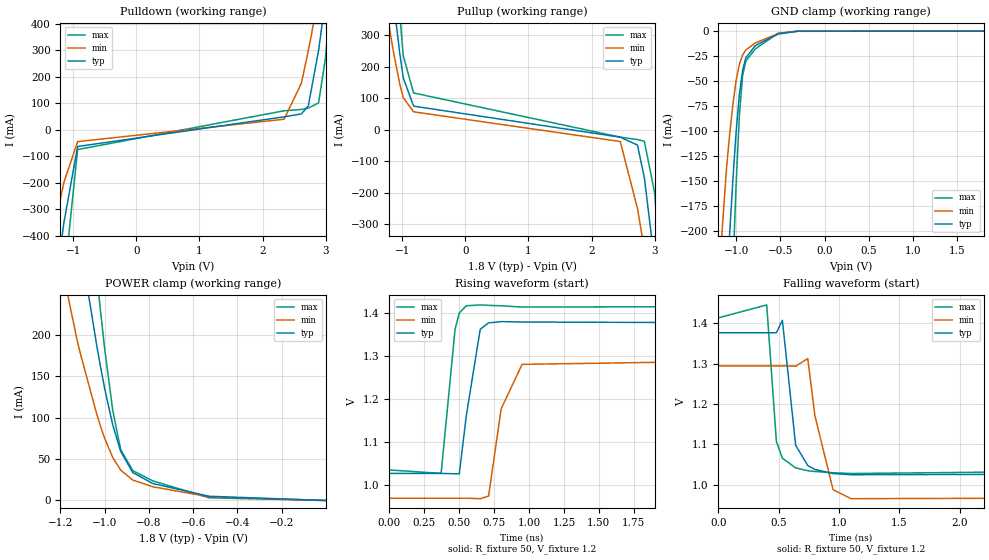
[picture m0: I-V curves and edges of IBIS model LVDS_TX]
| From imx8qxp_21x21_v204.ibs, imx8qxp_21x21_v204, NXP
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[Model]   LVDS_TX
Model_type   3-state
Polarity   Non-Inverting
Enable   Active-High
Vmeas =   1.2
Cref =   5p
Rref =   50
Vref =   1.2
|   typ   min   max
C_comp  7.96p   7.75p   8.18p
[Temperature Range]   85   125   -40
[Voltage Range]   1.8   1.52   1.98
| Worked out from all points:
|   slope of the pulldown table from 0 to 0.27 V, typ, clamps not added: 132 ohm
|   slope of the pullup table from 0 to 0.27 V, typ, clamps not added: 23.6 ohm
|   GND clamp passes 1 mA (typ) near -0.44 V on its own axis
|   POWER clamp passes 1 mA (typ) near -0.38 V on its own axis
|   falling waveform, R_fixture 50, V_fixture 1.2: 20-80 % time 76.9ps typ, 133ps min, 53.3ps max; typ from 1.38 V to 1.03 V
|   rising waveform, R_fixture 50, V_fixture 1.2: 20-80 % time 72.6ps typ, 133ps min, 65.3ps max; typ from 1.03 V to 1.38 V
[GND_clamp]
|Voltage   I (typ)   I (min)   I (max)
-1.8V     -1.612A    -1.003A    -2.601A
-1.109V   -260.3mA   -136.7mA   -435.1mA
-1.073V   -201.1mA   -102.2mA   -333.3mA
-1.036V   -146.9mA   -72.45mA   -237.4mA
-1V       -99.85mA   -49.02mA   -151.6mA
-963.7mV  -63.22mA   -33.06mA   -84mA
-927.4mV  -39.27mA   -23.8mA    -44.52mA
-891mV    -26.52mA   -18.76mA   -29.65mA
-781.9mV  -14.28mA   -11.66mA   -17.57mA
-527.4mV  -2.88mA    -2.497mA   -2.095mA
-309.2mV  -53.45uA   -70.95uA   -1.209uA
1.8V      36.67nA    192.5uA    5.567nA
[Power_clamp]
|Volatge   I (typ)   I (min)   I (max)
-1.8V     1.693A     1.071A     2.696A
-1.127V   340.2mA    196.7mA    531mA
-1.109V   308mA      176.8mA    477.4mA
-1.036V   187.7mA    104.6mA    273.7mA
-1.018V   160.7mA    89.11mA    227.2mA
-1V       135.4mA    75.08mA    183.6mA
-963.7mV  91.59mA    52.14mA    109.4mA
-927.4mV  59.34mA    36.68mA    61.46mA
-872.8mV  33.76mA    24.71mA    36.12mA
-781.9mV  20.48mA    16.58mA    23.71mA
-527.4mV  5.097mA    4.472mA    3.25mA
-180uV    37.51nA    91.89nA    11.1nA
[Pulldown]
|Volatge   I (typ)   I (min)   I (max)
-1.8V     -1.644A    -1.031A    -2.638A
-1.364V   -763.9mA   -460.1mA   -1.247A
-1.2V     -450mA     -260.2mA   -740.1mA
-1.146V   -351mA     -198.8mA   -576.4mA
-928mV    -63.45mA   -44.97mA   -74.87mA
2.342V    48.7mA     39.51mA    71.34mA
2.615V    59.54mA    175.4mA    76.45mA
2.724V    89.45mA    297.1mA    81.35mA
2.887V    297.8mA    498.9mA    101mA
2.996V    491.6mA    639.6mA    269.8mA
3.105V    699.3mA    783mA      566.7mA
3.595V    1.692A     1.447A     2.106A
[Pullup]
|Volatge   I (typ)   I (min)   I (max)
-1.8V     1.741A     1.108A     2.775A
-1.309V   738.4mA    456mA      1.184A
-1.146V   426.3mA    257.2mA    676.6mA
-1.036V   240.8mA    144.3mA    365.2mA
-981.9mV  165mA      102.1mA    235.1mA
-818.3mV  74.95mA    56.85mA    116.8mA
2.454V    -23.73mA   -37.59mA   -23.66mA
2.727V    -48.82mA   -250.5mA   -31.47mA
2.836V    -152.9mA   -380.5mA   -36.62mA
3V        -424.3mA   -586.8mA   -201.8mA
3.109V    -629.3mA   -728.2mA   -494.9mA
3.599V    -1.612A    -1.381A    -2.021A
[Ramp]
|variable   typ   min   max
dV/dt_r   211m/73p   228m/65p   197m/91p
dV/dt_f   211m/78p   228m/54p   197m/92p
R_load  = 50
[Falling waveform]
R_fixture = 50
V_fixture = 1.2
|time   V (typ)   V (min)   V (max)
0s        1.377V     1.295V     1.414V
400ps     1.377V     1.295V     1.446V
480ps     1.377V     1.295V     1.108V
530ps     1.408V     1.295V     1.066V
640ps     1.098V     1.294V     1.042V
740ps     1.048V     1.313V     1.035V
800ps     1.038V     1.171V     1.033V
950ps     1.028V     988.1mV    1.03V
1.1ns     1.025V     965.6mV    1.028V
3.8ns     1.027V     967.9mV    1.036V
[Rising waveform]
R_fixture = 50
V_fixture = 1.2
|time   V (typ)   V (min)   V (max)
0s        1.026V     967.9mV    1.034V
370ps     1.026V     967.9mV    1.026V
470ps     1.025V     967.9mV    1.363V
500ps     1.025V     967.9mV    1.401V
550ps     1.16V      967.9mV    1.418V
650ps     1.363V     966.8mV    1.42V
710ps     1.378V     973mV      1.419V
800ps     1.381V     1.177V     1.418V
950ps     1.38V      1.281V     1.415V
3.8ns     1.377V     1.295V     1.417V
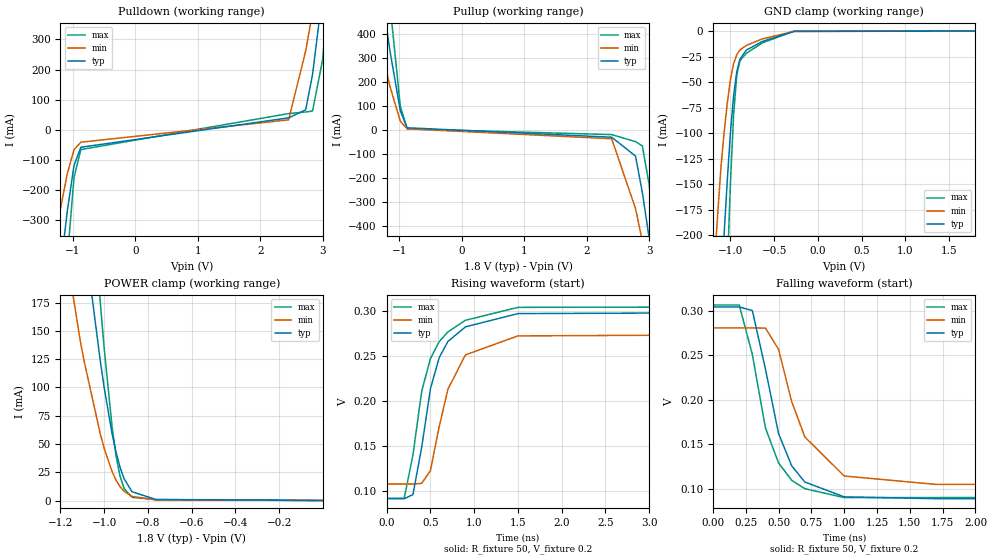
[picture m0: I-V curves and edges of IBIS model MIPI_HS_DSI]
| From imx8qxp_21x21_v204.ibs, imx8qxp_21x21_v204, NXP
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[Model]   MIPI_HS_DSI
Model_type   Output
Polarity   Non-Inverting
Enable   Active-High
Vmeas =   0.2
|Cref =   0
Rref =   50
|   typ   min   max
C_comp  7.96p   7.75p   8.18p
[Temperature Range]   85   125   -40
[Voltage Range]   1.8  1.52  1.98
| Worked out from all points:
|   slope of the pulldown table from 0 to 0.27 V, typ, clamps not added: 43.5 ohm
|   slope of the pullup table from 0 to 0.27 V, typ, clamps not added: 20.3 kohm
|   GND clamp passes 1 mA (typ) near -0.33 V on its own axis
|   POWER clamp passes 1 mA (typ) near -0.77 V on its own axis
|   falling waveform, R_fixture 50, V_fixture 0.2: 20-80 % time 218ps typ, 250ps min, 207ps max; typ from 0.304 V to 0.092 V
|   rising waveform, R_fixture 50, V_fixture 0.2: 20-80 % time 303ps typ, 323ps min, 299ps max; typ from 0.092 V to 0.304 V
[GND_clamp]
|Voltage   I (typ)   I (min)   I (max)
-1.8V     -1.608A    -995.2mA   -2.596A
-1.109V   -258.7mA   -133.8mA   -430.2mA
-1.073V   -199.9mA   -99.74mA   -329mA
-1.036V   -146mA     -70.4mA    -233.7mA
-1V       -99.47mA   -47.42mA   -148.6mA
-963.7mV  -63.29mA   -31.91mA   -81.65mA
-927.4mV  -39.79mA   -23.08mA   -42.92mA
-891mV    -27.48mA   -18.47mA   -28.89mA
-818.3mV  -18.6mA    -14.04mA   -21.73mA
-636.5mV  -10.18mA   -7.724mA   -11.63mA
-272.9mV  -360.4uA   -288.5uA   -68.59uA
1.8V      29.12uA    51.4uA     11.28uA
[Power_clamp]
|Volatge   I (typ)   I (min)   I (max)
-1.8V     1.584A     981.6mA    2.537A
-1.109V   263.6mA    140.7mA    414.1mA
-1.091V   233.6mA    122.6mA    363.6mA
-1.018V   123.6mA    58.92mA    175.6mA
-1V       99.74mA    46.06mA    134.3mA
-963.7mV  58.73mA    25.42mA    64.71mA
-945.5mV  42.39mA    17.9mA     39.21mA
-927.4mV  29.25mA    12.22mA    21.38mA
-909.2mV  19.34mA    8.156mA    10.74mA
-872.8mV  7.764mA    3.577mA    2.807mA
-763.7mV  909.8uA    638.9uA    798uA
-180uV    29.14uA    19uA       18.23uA
[Pulldown]
|Volatge   I (typ)   I (min)   I (max)
-1.8V     -1.664A    -1.035A    -2.668A
-1.364V   -778.8mA   -463mA     -1.263A
-1.2V     -464.1mA   -263.4mA   -752.8mA
-1.091V   -271.2mA   -146.3mA   -430mA
-982.5mV  -118.6mA   -66.21mA   -158.1mA
-873.5mV  -58.3mA    -41.54mA   -65.92mA
2.451V    39.38mA    32.76mA    53.56mA
2.724V    66.15mA    262mA      59.11mA
2.833V    182.9mA    389.3mA    61.89mA
2.996V    454.3mA    589.6mA    233.2mA
3.105V    655.4mA    726.6mA    523.4mA
3.595V    1.615A     1.358A     2.026A
[Pullup]
|Volatge   I (typ)   I (min)   I (max)
-1.8V     1.584A     981.8mA    2.537A
-1.364V   727.5mA    431.7mA    1.172A
-1.2V     422.4mA    238.8mA    677.2mA
-1.146V   325.8mA    178.7mA    517.8mA
-981.9mV  78.26mA    35.02mA    97.33mA
-872.8mV  8.042mA    3.769mA    3.226mA
2.4V      -31.26mA   -37.7mA    -20.36mA
2.781V    -109.7mA   -328.4mA   -49.76mA
2.89V     -260.4mA   -463.5mA   -67.15mA
3V        -452.3mA   -603.1mA   -229mA
3.109V    -659.4mA   -745.4mA   -526mA
3.599V    -1.65A     -1.399A    -2.068A
[Ramp]
|variable typ   min   max
dV/dt_r   127m/301p   106m/317p   132m/309p
dV/dt_f   130m/204p   107m/253p   128m/197p
R_load  = 50
[Falling waveform]
R_fixture = 50
V_fixture = 0.2
|time   V (typ)   V (min)   V (max)
0s        304mV      280.5mV    306.3mV
200ps     304mV      280.5mV    306.3mV
300ps     300mV      280.5mV    250.8mV
400ps     234.3mV    280.3mV    168.2mV
500ps     161.8mV    256.4mV    128.8mV
600ps     125.7mV    197.8mV    109.4mV
700ps     107.5mV    158.1mV    99.99mV
1ns       90.8mV     114.2mV    90.01mV
1.7ns     88.76mV    104.8mV    90.03mV
20ns      91.7mV     107.9mV    92.21mV
[Rising waveform]
R_fixture = 50
V_fixture = 0.2
|time   V (typ)   V (min)   V (max)
0s        91.73mV    108mV      92.21mV
200ps     91.73mV    108mV      92.21mV
300ps     96.27mV    108mV      140.2mV
400ps     148.7mV    108.7mV    210.8mV
500ps     213.5mV    122.8mV    246.9mV
600ps     248mV      171.5mV    265.7mV
700ps     265.9mV    213mV      276.4mV
900ps     282mV      251mV      289.3mV
1.5ns     296.7mV    272mV      303.6mV
20ns      303.9mV    280.4mV    306.3mV
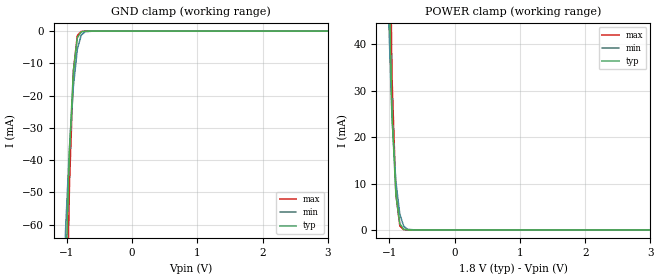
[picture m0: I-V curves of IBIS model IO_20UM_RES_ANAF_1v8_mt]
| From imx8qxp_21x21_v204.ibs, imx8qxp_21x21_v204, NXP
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[Model]  IO_20UM_RES_ANAF_1v8_mt
|   Model IO_20UM_RES_ANAF_1v8_mt
| This model was characterised for following simulation conditions:
| External (pad) voltage:
|   - Typ: 1.8V,   - Min: 1.62V,   - Max: 1.98V
| Library cells for typ/min/max conditions are connected as defined below:
|  IOPAD - External Pad
|  ANAIO - NC
|  ANA_Z20 - NC
|  ANA_Z200_1 - NC
|  ANA_Z200_2 - NC
|  ANA_Z40_1 - NC
|  ANA_Z40_2 - NC
|  PDRV - gnd
|  PSW - vdd
|  esdsub - 0
|  gnd - gnd
|  gnde - gnde
|  vdd - vdd
|  vdde - vdde
| All other pins connected to ground
Model_type Terminator
C_comp   0.5533pF   0.5015pF   0.6178pF
|C_comp_pullup   0.2711pF   0.2913pF   0.2556pF
|C_comp_pulldown   0.2605pF   0.3048pF   0.2242pF
[Temperature Range]   25.0000   0.1050k   -20.0000
[Voltage Range]   1.8000V   1.6200V   1.9800V
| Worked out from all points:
|   GND clamp passes 1 mA (typ) near -0.80 V on its own axis
|   POWER clamp passes 1 mA (typ) near -0.82 V on its own axis
[GND_clamp]
|Voltage   I(typ)   I(min)   I(max)
-1.98V    -2.02A     -1.155A    -3.362A
-1.02V    -77.29mA   -61.73mA   -110.4mA
-960mV    -37.3mA    -35.96mA   -47.41mA
-900mV    -12.29mA   -17.09mA   -12.41mA
-840mV    -2.105mA   -5.644mA   -1.332mA
-780mV    -230.3uA   -1.233mA   -91.03uA
-720mV    -22.65uA   -212.5uA   -5.854uA
-600mV    -213.2nA   -5.457uA   -24nA
3.96V     0A         0A         0A
[POWER_clamp]
|Voltage   I(typ)   I(min)   I(max)
-1.98V    2.08A      1.18A      3.485A
-1.02V    64.69mA    49.61mA    101.3mA
-960mV    25.01mA    24.2mA     32.98mA
-900mV    7.542mA    10.33mA    7.783mA
-840mV    1.355mA    3.392mA    887.3uA
-780mV    153.4uA    779.1uA    61.99uA
-720mV    15.16uA    137.9uA    3.993uA
-600mV    142.7nA    3.566uA    16.38nA
3.96V     0A         0A         0A
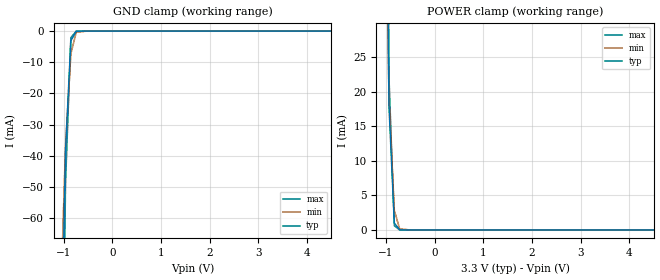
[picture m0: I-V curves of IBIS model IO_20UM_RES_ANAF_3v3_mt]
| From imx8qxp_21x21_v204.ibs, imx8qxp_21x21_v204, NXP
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[Model]  IO_20UM_RES_ANAF_3v3_mt
|   Model IO_20UM_RES_ANAF_3v3_mt
| This model was characterised for following simulation conditions:
| External (pad) voltage:
|   - Typ: 3.3V,   - Min: 3.0V,   - Max: 3.6V
| Library cells for typ/min/max conditions are connected as defined below:
|  IOPAD - External Pad
|  ANAIO - NC
|  ANA_Z20 - NC
|  ANA_Z200_1 - NC
|  ANA_Z200_2 - NC
|  ANA_Z40_1 - NC
|  ANA_Z40_2 - NC
|  PDRV - gnd
|  PSW - vdd
|  esdsub - 0
|  gnd - gnd
|  gnde - gnde
|  vdd - vdd
|  vdde - vdde
| All other pins connected to ground
Model_type Terminator
C_comp   0.5469pF   0.4975pF   0.6083pF
|C_comp_pullup   0.2647pF   0.2818pF   0.2515pF
|C_comp_pulldown   0.2605pF   0.3048pF   0.2242pF
[Temperature Range]   25.0000   0.1050k   -20.0000
[Voltage Range]   3.3000V   3.0000V   3.6000V
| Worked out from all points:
|   GND clamp passes 1 mA (typ) near -0.77 V on its own axis
|   POWER clamp passes 1 mA (typ) near -0.83 V on its own axis
[GND_clamp]
|Voltage   I(typ)   I(min)   I(max)
-3.6V     -5.645A    -3.235A    -9.348A
-1.07V    -128.2mA   -91.59mA   -198.7mA
-960mV    -38.55mA   -37.05mA   -49.07mA
-850mV    -3.081mA   -7.268mA   -2.133mA
-740mV    -51.6uA    -404uA     -15.39uA
-520mV    -9.966nA   -491.3nA   -669.1pA
7.2V      0A         0A         0A
[POWER_clamp]
|Voltage   I(typ)   I(min)   I(max)
-3.6V     5.792A     3.291A     9.643A
-1.05V    98.58mA    69.05mA    162.9mA
-940mV    17.91mA    19.01mA    22.12mA
-830mV    1.003mA    2.816mA    604.5uA
-720mV    15.8uA     143.5uA    4.172uA
-500mV    3.085nA    173.1nA    527pA
7.2V      0A         0A         0A
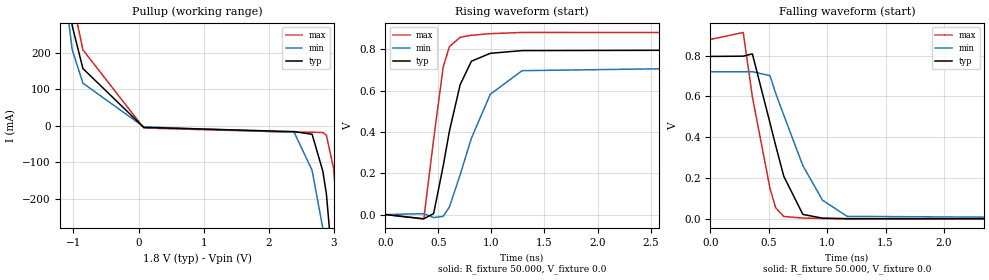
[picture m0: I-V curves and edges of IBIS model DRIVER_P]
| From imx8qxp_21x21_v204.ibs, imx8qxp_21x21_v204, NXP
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[Model] DRIVER_P
Model_type Open_source
Polarity   Non-Inverting
Enable   Active-High
Rref =  50.000
C_comp   0.765pF   0.689pF   0.872pF
C_comp_pullup   0.231pF   0.216pF   0.259pF
C_comp_gnd_clamp   0.135pF   0.114pF   0.160pF
[Temperature Range]   25.000   0.125k   -40.000
[Voltage Range]   1.800V   1.620V   1.980V
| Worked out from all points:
|   slope of the pullup table from 0 to 0.27 V, typ, clamps not added: 18.1 ohm
|   rising waveform, R_fixture 50.000, V_fixture 0.0: 20-80 % time 191ps typ, 308ps min, 125ps max; typ from 0 V to 0.798 V
|   falling waveform, R_fixture 50.000, V_fixture 0.0: 20-80 % time 233ps typ, 313ps min, 176ps max; typ from 0.796 V to 0 V
[Pullup]
|Voltage   I(typ)   I(min)   I(max)
-1.8V     6.228A     3.398A     10.87A
-1.13V    562.8mA    367.8mA    869.2mA
-1.02V    274.1mA    208.6mA    347.7mA
-855mV    156.7mA    116.7mA    207.9mA
80mV      -4.501mA   -3.057mA   -6.132mA
2.39V     -16.02mA   -18.03mA   -17.69mA
2.665V    -23.31mA   -122mA     -17.69mA
2.83V     -124.4mA   -281.1mA   -18.42mA
2.885V    -187.2mA   -372.5mA   -26.07mA
2.995V    -413.1mA   -653.9mA   -116.8mA
3.105V    -917.3mA   -1.067A    -347.2mA
3.6V      -5.151A    -3.496A    -6.598A
[Ramp]
| variable   typ   min   max
dV/dt_r   0.479/0.191n   0.433/0.308n   0.528/0.125n
dV/dt_f   0.477/0.233n   0.433/0.313n   0.527/0.176n
R_load = 50.000
[Rising Waveform]
R_fixture= 50.000
V_fixture= 0.0
V_fixture_min= 0.0
V_fixture_max= 0.0
|time   V(typ)   V(min)   V(max)
0s        21.96nV    2.305uV    46.66nV
362ps     -20.44mV   4.33mV     -21.78mV
455ps     4.727mV    -14.63mV   364.1mV
545ps     234.9mV    -8.594mV   713.8mV
604ps     404.3mV    36.61mV    812.6mV
705ps     628.5mV    192.9mV    857.9mV
811ps     742mV      369.2mV    867.6mV
989ps     780.3mV    582mV      875.4mV
1.289ns   793.4mV    696.3mV    881.2mV
5ns       797.5mV    722.2mV    880.8mV
[Falling Waveform]
R_fixture= 50.000
V_fixture= 0.0
V_fixture_min= 0.0
V_fixture_max= 0.0
|time   V(typ)   V(min)   V(max)
0s        795.7mV    720.9mV    878.6mV
282ps     796.9mV    720.8mV    912.9mV
360ps     808.2mV    721.1mV    598.2mV
511ps     470mV      701.5mV    149.4mV
559ps     360.8mV    616.3mV    55.53mV
629ps     209mV      507.7mV    12.49mV
792ps     22.74mV    261.4mV    4.829mV
960ps     4.355mV    92.57mV    2.517mV
1.17ns    2.112mV    13.34mV    1.125mV
5ns       12.55uV    20.63uV    8.614uV
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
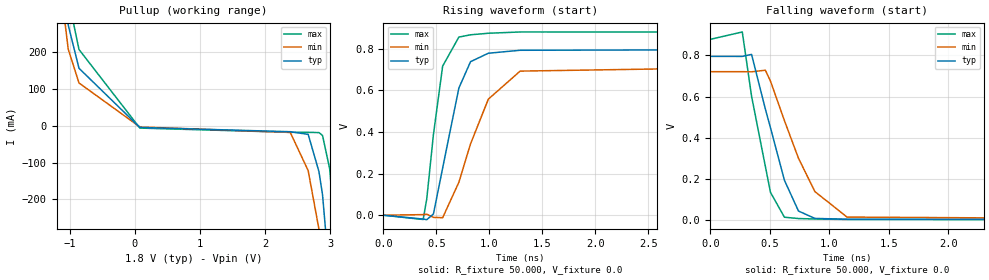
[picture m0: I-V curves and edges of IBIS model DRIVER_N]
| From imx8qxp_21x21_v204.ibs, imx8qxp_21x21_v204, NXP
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|   Model DRIVER_N
[Model] DRIVER_N
Model_type Open_source
Polarity   Inverting
Enable   Active-High
Rref =  50.000
C_comp   0.771pF   0.696pF   0.877pF
C_comp_pullup   0.230pF   0.215pF   0.258pF
C_comp_gnd_clamp   0.139pF   0.118pF   0.164pF
[Temperature Range]   25.000   0.125k   -40.000
[Voltage Range]   1.800V   1.620V   1.980V
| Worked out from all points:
|   slope of the pullup table from 0 to 0.27 V, typ, clamps not added: 18.1 ohm
|   rising waveform, R_fixture 50.000, V_fixture 0.0: 20-80 % time 191ps typ, 309ps min, 125ps max; typ from 0 V to 0.798 V
|   falling waveform, R_fixture 50.000, V_fixture 0.0: 20-80 % time 231ps typ, 308ps min, 176ps max; typ from 0.796 V to 0 V
[Pullup]
|Voltage   I(typ)   I(min)   I(max)
-1.8V     6.228A     3.398A     10.87A
-1.13V    562.8mA    367.8mA    869.2mA
-1.02V    274.1mA    208.6mA    347.7mA
-855mV    156.7mA    116.7mA    207.9mA
80mV      -4.501mA   -3.057mA   -6.132mA
2.39V     -16.02mA   -18.03mA   -17.69mA
2.665V    -23.31mA   -122mA     -17.69mA
2.83V     -124.4mA   -281.1mA   -18.42mA
2.885V    -187.2mA   -372.5mA   -26.07mA
2.995V    -413.1mA   -653.9mA   -116.8mA
3.105V    -917.3mA   -1.067A    -347.2mA
3.6V      -5.151A    -3.496A    -6.598A
[Ramp]
| variable   typ   min   max
dV/dt_r   0.479/0.191n   0.433/0.309n   0.528/0.125n
dV/dt_f   0.477/0.231n   0.433/0.308n   0.527/0.177n
R_load = 50.000
[Rising Waveform]
R_fixture= 50.000
V_fixture= 0.0
V_fixture_min= 0.0
V_fixture_max= 0.0
|time   V(typ)   V(min)   V(max)
0s        21.96nV    2.305uV    46.66nV
375ps     -18.5mV    2.858mV    -20.62mV
409ps     -21.51mV   4.9mV      78.08mV
472ps     6.119mV    -10.46mV   388mV
559ps     227mV      -12.02mV   717mV
712ps     611.7mV    158.3mV    856.6mV
822ps     738.2mV    343.3mV    867.5mV
990ps     778.9mV    558.1mV    875mV
1.29ns    793.1mV    692.9mV    881.1mV
5ns       797.5mV    722.3mV    880.8mV
[Falling Waveform]
R_fixture= 50.000
V_fixture= 0.0
V_fixture_min= 0.0
V_fixture_max= 0.0
|time   V(typ)   V(min)   V(max)
0s        795.7mV    720.9mV    878.6mV
269ps     795.5mV    721.1mV    914.5mV
347ps     805.2mV    720.3mV    601.5mV
463ps     538.6mV    728.2mV    259mV
506ps     447.7mV    674.7mV    133.1mV
623ps     192.3mV    482.8mV    12.02mV
741ps     42.26mV    299.5mV    5.595mV
879ps     6.215mV    137mV      3.333mV
1.149ns   2.155mV    12.71mV    1.166mV
5ns       11.91uV    17.21uV    8.383uV
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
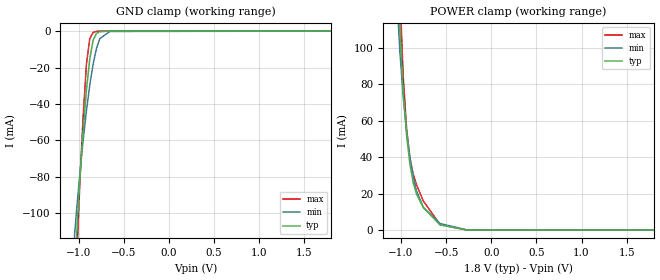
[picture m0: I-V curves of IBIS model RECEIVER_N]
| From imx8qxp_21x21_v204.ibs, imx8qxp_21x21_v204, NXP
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|   Model RECEIVER_N
[Model] RECEIVER_N
Model_type Input
Polarity   Non-Inverting
Enable   Active-High
Vinl =  0.250V
Vinh =  0.550V
C_comp   0.562pF   0.488pF   0.664pF
C_comp_power_clamp   0.190pF   0.177pF   0.208pF
[Temperature Range]   25.000   0.125k   -40.000
[Voltage Range]   1.800V   1.620V   1.980V
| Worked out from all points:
|   GND clamp passes 1 mA (typ) near -0.79 V on its own axis
|   POWER clamp passes 1 mA (typ) near -0.48 V on its own axis
[GND_clamp]
|Voltage   I(typ)   I(min)   I(max)
-1.8V     -5.099A    -2.527A    -9.425A
-1.06V    -152.3mA   -122.3mA   -189.3mA
-1.023V   -113.9mA   -99.1mA    -130.1mA
-986mV    -81.79mA   -78.56mA   -83.9mA
-949mV    -54.55mA   -60.16mA   -47.16mA
-912mV    -32.22mA   -43.74mA   -18.09mA
-875mV    -15.24mA   -29.55mA   -4.084mA
-838mV    -4.964mA   -18.1mA    -736uA
-801mV    -1.343mA   -9.565mA   -124.9uA
-764mV    -339.3uA   -4.124mA   -20.53uA
-653mV    -4.851uA   -200.6uA   -182.1nA
1.8V      0A         0A         -12.74pA
[POWER_clamp]
|Voltage   I(typ)   I(min)   I(max)
-1.8V     6.019A     3.248A     10.61A
-1.049V   163mA      130.9mA    208mA
-1.012V   110.9mA    97.43mA    130.1mA
-975mV    76.15mA    72.67mA    83.97mA
-938mV    52.2mA     53.95mA    55.61mA
-901mV    36.03mA    39.68mA    39.4mA
-864mV    25.87mA    29.02mA    30.55mA
-827mV    19.66mA    21.38mA    24.74mA
-753mV    12.35mA    12.44mA    15.9mA
-568mV    2.795mA    3.547mA    3.03mA
-272mV    5.718uA    67.54uA    929.7nA
1.8V      0A         0A         0A
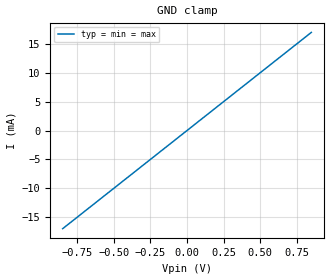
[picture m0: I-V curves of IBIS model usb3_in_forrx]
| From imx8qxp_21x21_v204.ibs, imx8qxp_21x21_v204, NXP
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[Model]   usb3_in_forrx
Model_type  Input
Vinl=0.1
Vinh=0.1
| variable   typ   min   max
C_comp   1.5pF   1.2pF   1.8pF
[Temperature Range]   27   -40   125
[Voltage range]   1   0.8   1.2
[GND Clamp]
|  Voltage   I(typ)   I(min)   I(max)
-850mV    -17mA      -17mA      -17mA
0V        0A         0A         0A
850mV     17mA       17mA       17mA
[Algorithmic Model]
Executable Windows_VisualStudio7.1.3088_32 rx_win32_rev1.dll usb3_rx_rev1.ami
Executable Windows_VisualStudio10.0.30319_64 rx_win64_rev1.dll usb3_rx_rev1.ami
Executable Linux_gcc4.1.2_64 rx_rev1.so usb3_rx_rev1.ami
[End Algorithmic Model]
| End [Model] usb3_in_forrx
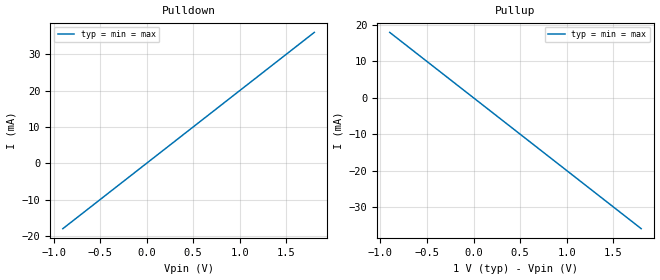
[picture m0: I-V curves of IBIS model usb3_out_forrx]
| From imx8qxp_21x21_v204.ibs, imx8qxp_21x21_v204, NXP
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[Model]   usb3_out_forrx
Model_type  Output
Polarity Non-Inverting
Vmeas =   0.2
| variable   typ   min   max
C_comp   1.0fF   1.0fF   1.0fF
[Temperature Range]   27   -40   125
[Voltage range]   1.00   1.00   1.00
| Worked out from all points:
|   slope of the pulldown table from 0 to 0.15 V, typ, clamps not added: 50 ohm
|   slope of the pullup table from 0 to 0.15 V, typ, clamps not added: 50 ohm
| Launch Voltage for (TYP, MIN, MAX = 0.972, 0.822, 1.11)
[Pulldown]
|  Voltage   I(typ)   I(min)   I(max)
-900mV    -18mA      -18mA      -18mA
0V        0A         0A         0A
1.8V      36mA       36mA       36mA
[Pullup]
|  Voltage   I(typ)   I(min)   I(max)
-900mV    18mA       18mA       18mA
0V        0A         0A         0A
1.8V      -36mA      -36mA      -36mA
[Ramp]
| variable   typ   min   max
dV/dt_r   0.624/0.131E-09   0.624/0.131E-09   0.624/0.131E-09
dV/dt_f   0.624/0.131E-09   0.624/0.131E-09   0.624/0.131E-09
R_load = 50
[Algorithmic Model]
Executable Windows_VisualStudio7.1.3088_32 tx_win32_rev1.dll usb3_tx_rev1.ami
Executable Windows_VisualStudio10.0.30319_64 tx_win64_rev1.dll usb3_tx_rev1.ami
Executable Linux_gcc4.1.2_64 tx_rev1.so usb3_tx_rev1.ami
[End Algorithmic Model]
| End [Model] usb3_out_forrx
